VERSION 5.8 ;
BUSBITCHARS "[]" ;
DIVIDERCHAR "/" ;
UNITS
    DATABASE MICRONS 1000 ;
END UNITS

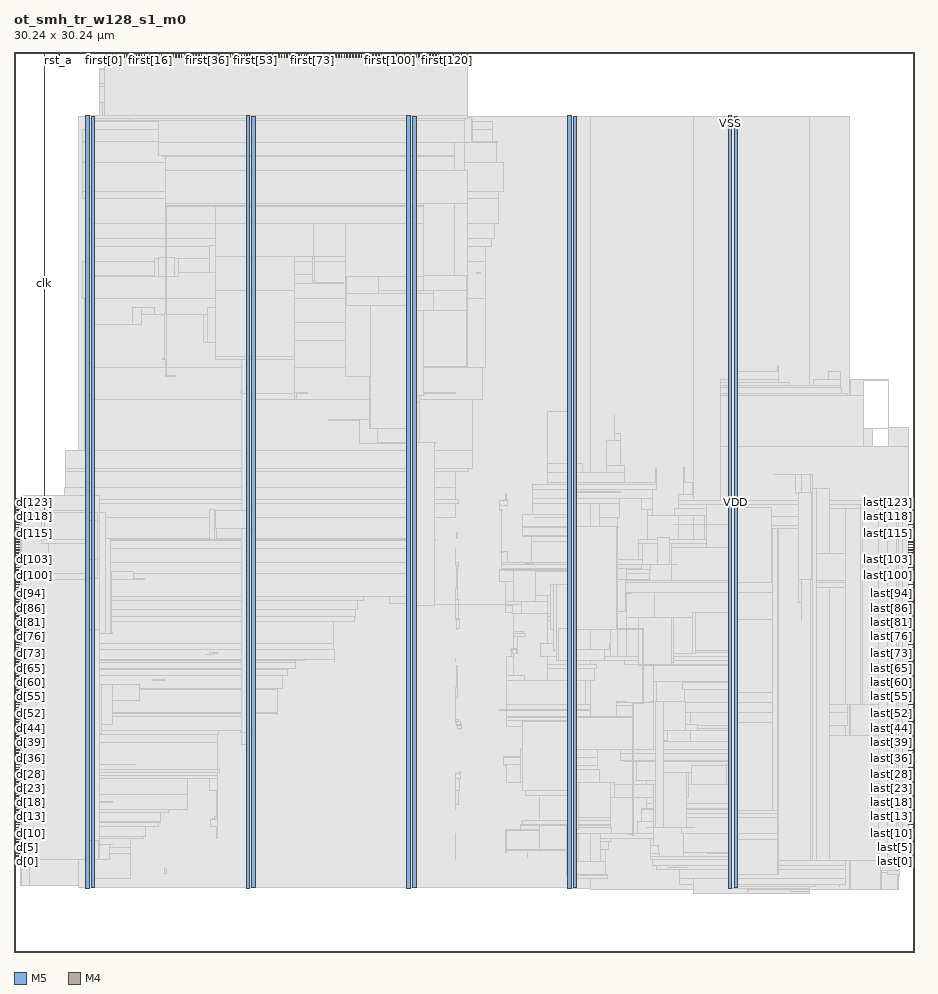
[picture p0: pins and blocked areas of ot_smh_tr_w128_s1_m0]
MACRO ot_smh_tr_w128_s1_m0
  FOREIGN ot_smh_tr_w128_s1_m0 0 0 ;
  CLASS BLOCK ;
  SIZE 30.24 BY 30.24 ;
  PIN clk
    DIRECTION INPUT ;
    USE SIGNAL ;
    PORT
      LAYER M5 ;
        RECT  1.008 30.048 1.032 30.24 ;
    END
    PORT
      LAYER M5 ;
        RECT  1.008 14.819 1.032 30.096 ;
    END
  END clk
  PIN d[0]
    DIRECTION INPUT ;
    USE SIGNAL ;
    PORT
      LAYER M4 ;
        RECT  0 3.024 0.192 3.048 ;
    END
  END d[0]
  PIN d[100]
    DIRECTION INPUT ;
    USE SIGNAL ;
    PORT
      LAYER M4 ;
        RECT  0 12.624 0.192 12.648 ;
    END
  END d[100]
  PIN d[101]
    DIRECTION INPUT ;
    USE SIGNAL ;
    PORT
      LAYER M4 ;
        RECT  0 12.72 0.192 12.744 ;
    END
  END d[101]
  PIN d[102]
    DIRECTION INPUT ;
    USE SIGNAL ;
    PORT
      LAYER M4 ;
        RECT  0 12.816 0.192 12.84 ;
    END
  END d[102]
  PIN d[103]
    DIRECTION INPUT ;
    USE SIGNAL ;
    PORT
      LAYER M4 ;
        RECT  0 12.912 0.192 12.936 ;
    END
  END d[103]
  PIN d[104]
    DIRECTION INPUT ;
    USE SIGNAL ;
    PORT
      LAYER M4 ;
        RECT  0 13.008 0.192 13.032 ;
    END
  END d[104]
  PIN d[105]
    DIRECTION INPUT ;
    USE SIGNAL ;
    PORT
      LAYER M4 ;
        RECT  0 13.104 0.192 13.128 ;
    END
  END d[105]
  PIN d[106]
    DIRECTION INPUT ;
    USE SIGNAL ;
    PORT
      LAYER M4 ;
        RECT  0 13.2 0.192 13.224 ;
    END
  END d[106]
  PIN d[107]
    DIRECTION INPUT ;
    USE SIGNAL ;
    PORT
      LAYER M4 ;
        RECT  0 13.296 0.192 13.32 ;
    END
  END d[107]
  PIN d[108]
    DIRECTION INPUT ;
    USE SIGNAL ;
    PORT
      LAYER M4 ;
        RECT  0 13.392 0.192 13.416 ;
    END
  END d[108]
  PIN d[109]
    DIRECTION INPUT ;
    USE SIGNAL ;
    PORT
      LAYER M4 ;
        RECT  0 13.488 0.192 13.512 ;
    END
  END d[109]
  PIN d[10]
    DIRECTION INPUT ;
    USE SIGNAL ;
    PORT
      LAYER M4 ;
        RECT  0 3.984 0.192 4.008 ;
    END
  END d[10]
  PIN d[110]
    DIRECTION INPUT ;
    USE SIGNAL ;
    PORT
      LAYER M4 ;
        RECT  0 13.584 0.192 13.608 ;
    END
  END d[110]
  PIN d[111]
    DIRECTION INPUT ;
    USE SIGNAL ;
    PORT
      LAYER M4 ;
        RECT  0 13.68 0.192 13.704 ;
    END
  END d[111]
  PIN d[112]
    DIRECTION INPUT ;
    USE SIGNAL ;
    PORT
      LAYER M4 ;
        RECT  0 13.776 0.192 13.8 ;
    END
  END d[112]
  PIN d[113]
    DIRECTION INPUT ;
    USE SIGNAL ;
    PORT
      LAYER M4 ;
        RECT  0 13.872 0.192 13.896 ;
    END
  END d[113]
  PIN d[114]
    DIRECTION INPUT ;
    USE SIGNAL ;
    PORT
      LAYER M4 ;
        RECT  0 13.968 0.192 13.992 ;
    END
  END d[114]
  PIN d[115]
    DIRECTION INPUT ;
    USE SIGNAL ;
    PORT
      LAYER M4 ;
        RECT  0 14.064 0.192 14.088 ;
    END
  END d[115]
  PIN d[116]
    DIRECTION INPUT ;
    USE SIGNAL ;
    PORT
      LAYER M4 ;
        RECT  0 14.16 0.192 14.184 ;
    END
  END d[116]
  PIN d[117]
    DIRECTION INPUT ;
    USE SIGNAL ;
    PORT
      LAYER M4 ;
        RECT  0 14.256 0.192 14.28 ;
    END
  END d[117]
  PIN d[118]
    DIRECTION INPUT ;
    USE SIGNAL ;
    PORT
      LAYER M4 ;
        RECT  0 14.352 0.192 14.376 ;
    END
  END d[118]
  PIN d[119]
    DIRECTION INPUT ;
    USE SIGNAL ;
    PORT
      LAYER M4 ;
        RECT  0 14.448 0.192 14.472 ;
    END
  END d[119]
  PIN d[11]
    DIRECTION INPUT ;
    USE SIGNAL ;
    PORT
      LAYER M4 ;
        RECT  0 4.08 0.192 4.104 ;
    END
  END d[11]
  PIN d[120]
    DIRECTION INPUT ;
    USE SIGNAL ;
    PORT
      LAYER M4 ;
        RECT  0 14.544 0.192 14.568 ;
    END
  END d[120]
  PIN d[121]
    DIRECTION INPUT ;
    USE SIGNAL ;
    PORT
      LAYER M4 ;
        RECT  0 14.64 0.192 14.664 ;
    END
  END d[121]
  PIN d[122]
    DIRECTION INPUT ;
    USE SIGNAL ;
    PORT
      LAYER M4 ;
        RECT  0 14.736 0.192 14.76 ;
    END
  END d[122]
  PIN d[123]
    DIRECTION INPUT ;
    USE SIGNAL ;
    PORT
      LAYER M4 ;
        RECT  0 14.832 0.192 14.856 ;
    END
  END d[123]
  PIN d[124]
    DIRECTION INPUT ;
    USE SIGNAL ;
    PORT
      LAYER M4 ;
        RECT  0 14.928 0.192 14.952 ;
    END
  END d[124]
  PIN d[125]
    DIRECTION INPUT ;
    USE SIGNAL ;
    PORT
      LAYER M4 ;
        RECT  0 15.024 0.192 15.048 ;
    END
  END d[125]
  PIN d[126]
    DIRECTION INPUT ;
    USE SIGNAL ;
    PORT
      LAYER M4 ;
        RECT  0 15.12 0.192 15.144 ;
    END
  END d[126]
  PIN d[127]
    DIRECTION INPUT ;
    USE SIGNAL ;
    PORT
      LAYER M4 ;
        RECT  0 15.216 0.192 15.24 ;
    END
  END d[127]
  PIN d[12]
    DIRECTION INPUT ;
    USE SIGNAL ;
    PORT
      LAYER M4 ;
        RECT  0 4.176 0.192 4.2 ;
    END
  END d[12]
  PIN d[13]
    DIRECTION INPUT ;
    USE SIGNAL ;
    PORT
      LAYER M4 ;
        RECT  0 4.272 0.192 4.296 ;
    END
  END d[13]
  PIN d[14]
    DIRECTION INPUT ;
    USE SIGNAL ;
    PORT
      LAYER M4 ;
        RECT  0 4.368 0.192 4.392 ;
    END
  END d[14]
  PIN d[15]
    DIRECTION INPUT ;
    USE SIGNAL ;
    PORT
      LAYER M4 ;
        RECT  0 4.464 0.192 4.488 ;
    END
  END d[15]
  PIN d[16]
    DIRECTION INPUT ;
    USE SIGNAL ;
    PORT
      LAYER M4 ;
        RECT  0 4.56 0.192 4.584 ;
    END
  END d[16]
  PIN d[17]
    DIRECTION INPUT ;
    USE SIGNAL ;
    PORT
      LAYER M4 ;
        RECT  0 4.656 0.192 4.68 ;
    END
  END d[17]
  PIN d[18]
    DIRECTION INPUT ;
    USE SIGNAL ;
    PORT
      LAYER M4 ;
        RECT  0 4.752 0.192 4.776 ;
    END
  END d[18]
  PIN d[19]
    DIRECTION INPUT ;
    USE SIGNAL ;
    PORT
      LAYER M4 ;
        RECT  0 4.848 0.192 4.872 ;
    END
  END d[19]
  PIN d[1]
    DIRECTION INPUT ;
    USE SIGNAL ;
    PORT
      LAYER M4 ;
        RECT  0 3.12 0.192 3.144 ;
    END
  END d[1]
  PIN d[20]
    DIRECTION INPUT ;
    USE SIGNAL ;
    PORT
      LAYER M4 ;
        RECT  0 4.944 0.192 4.968 ;
    END
  END d[20]
  PIN d[21]
    DIRECTION INPUT ;
    USE SIGNAL ;
    PORT
      LAYER M4 ;
        RECT  0 5.04 0.192 5.064 ;
    END
  END d[21]
  PIN d[22]
    DIRECTION INPUT ;
    USE SIGNAL ;
    PORT
      LAYER M4 ;
        RECT  0 5.136 0.192 5.16 ;
    END
  END d[22]
  PIN d[23]
    DIRECTION INPUT ;
    USE SIGNAL ;
    PORT
      LAYER M4 ;
        RECT  0 5.232 0.192 5.256 ;
    END
  END d[23]
  PIN d[24]
    DIRECTION INPUT ;
    USE SIGNAL ;
    PORT
      LAYER M4 ;
        RECT  0 5.328 0.192 5.352 ;
    END
  END d[24]
  PIN d[25]
    DIRECTION INPUT ;
    USE SIGNAL ;
    PORT
      LAYER M4 ;
        RECT  0 5.424 0.192 5.448 ;
    END
  END d[25]
  PIN d[26]
    DIRECTION INPUT ;
    USE SIGNAL ;
    PORT
      LAYER M4 ;
        RECT  0 5.52 0.192 5.544 ;
    END
  END d[26]
  PIN d[27]
    DIRECTION INPUT ;
    USE SIGNAL ;
    PORT
      LAYER M4 ;
        RECT  0 5.616 0.192 5.64 ;
    END
  END d[27]
  PIN d[28]
    DIRECTION INPUT ;
    USE SIGNAL ;
    PORT
      LAYER M4 ;
        RECT  0 5.712 0.192 5.736 ;
    END
  END d[28]
  PIN d[29]
    DIRECTION INPUT ;
    USE SIGNAL ;
    PORT
      LAYER M4 ;
        RECT  0 5.808 0.192 5.832 ;
    END
  END d[29]
  PIN d[2]
    DIRECTION INPUT ;
    USE SIGNAL ;
    PORT
      LAYER M4 ;
        RECT  0 3.216 0.192 3.24 ;
    END
  END d[2]
  PIN d[30]
    DIRECTION INPUT ;
    USE SIGNAL ;
    PORT
      LAYER M4 ;
        RECT  0 5.904 0.192 5.928 ;
    END
  END d[30]
  PIN d[31]
    DIRECTION INPUT ;
    USE SIGNAL ;
    PORT
      LAYER M4 ;
        RECT  0 6 0.192 6.024 ;
    END
  END d[31]
  PIN d[32]
    DIRECTION INPUT ;
    USE SIGNAL ;
    PORT
      LAYER M4 ;
        RECT  0 6.096 0.192 6.12 ;
    END
  END d[32]
  PIN d[33]
    DIRECTION INPUT ;
    USE SIGNAL ;
    PORT
      LAYER M4 ;
        RECT  0 6.192 0.192 6.216 ;
    END
  END d[33]
  PIN d[34]
    DIRECTION INPUT ;
    USE SIGNAL ;
    PORT
      LAYER M4 ;
        RECT  0 6.288 0.192 6.312 ;
    END
  END d[34]
  PIN d[35]
    DIRECTION INPUT ;
    USE SIGNAL ;
    PORT
      LAYER M4 ;
        RECT  0 6.384 0.192 6.408 ;
    END
  END d[35]
  PIN d[36]
    DIRECTION INPUT ;
    USE SIGNAL ;
    PORT
      LAYER M4 ;
        RECT  0 6.48 0.192 6.504 ;
    END
  END d[36]
  PIN d[37]
    DIRECTION INPUT ;
    USE SIGNAL ;
    PORT
      LAYER M4 ;
        RECT  0 6.576 0.192 6.6 ;
    END
  END d[37]
  PIN d[38]
    DIRECTION INPUT ;
    USE SIGNAL ;
    PORT
      LAYER M4 ;
        RECT  0 6.672 0.192 6.696 ;
    END
  END d[38]
  PIN d[39]
    DIRECTION INPUT ;
    USE SIGNAL ;
    PORT
      LAYER M4 ;
        RECT  0 6.768 0.192 6.792 ;
    END
  END d[39]
  PIN d[3]
    DIRECTION INPUT ;
    USE SIGNAL ;
    PORT
      LAYER M4 ;
        RECT  0 3.312 0.192 3.336 ;
    END
  END d[3]
  PIN d[40]
    DIRECTION INPUT ;
    USE SIGNAL ;
    PORT
      LAYER M4 ;
        RECT  0 6.864 0.192 6.888 ;
    END
  END d[40]
  PIN d[41]
    DIRECTION INPUT ;
    USE SIGNAL ;
    PORT
      LAYER M4 ;
        RECT  0 6.96 0.192 6.984 ;
    END
  END d[41]
  PIN d[42]
    DIRECTION INPUT ;
    USE SIGNAL ;
    PORT
      LAYER M4 ;
        RECT  0 7.056 0.192 7.08 ;
    END
  END d[42]
  PIN d[43]
    DIRECTION INPUT ;
    USE SIGNAL ;
    PORT
      LAYER M4 ;
        RECT  0 7.152 0.192 7.176 ;
    END
  END d[43]
  PIN d[44]
    DIRECTION INPUT ;
    USE SIGNAL ;
    PORT
      LAYER M4 ;
        RECT  0 7.248 0.192 7.272 ;
    END
  END d[44]
  PIN d[45]
    DIRECTION INPUT ;
    USE SIGNAL ;
    PORT
      LAYER M4 ;
        RECT  0 7.344 0.192 7.368 ;
    END
  END d[45]
  PIN d[46]
    DIRECTION INPUT ;
    USE SIGNAL ;
    PORT
      LAYER M4 ;
        RECT  0 7.44 0.192 7.464 ;
    END
  END d[46]
  PIN d[47]
    DIRECTION INPUT ;
    USE SIGNAL ;
    PORT
      LAYER M4 ;
        RECT  0 7.536 0.192 7.56 ;
    END
  END d[47]
  PIN d[48]
    DIRECTION INPUT ;
    USE SIGNAL ;
    PORT
      LAYER M4 ;
        RECT  0 7.632 0.192 7.656 ;
    END
  END d[48]
  PIN d[49]
    DIRECTION INPUT ;
    USE SIGNAL ;
    PORT
      LAYER M4 ;
        RECT  0 7.728 0.192 7.752 ;
    END
  END d[49]
  PIN d[4]
    DIRECTION INPUT ;
    USE SIGNAL ;
    PORT
      LAYER M4 ;
        RECT  0 3.408 0.192 3.432 ;
    END
  END d[4]
  PIN d[50]
    DIRECTION INPUT ;
    USE SIGNAL ;
    PORT
      LAYER M4 ;
        RECT  0 7.824 0.192 7.848 ;
    END
  END d[50]
  PIN d[51]
    DIRECTION INPUT ;
    USE SIGNAL ;
    PORT
      LAYER M4 ;
        RECT  0 7.92 0.192 7.944 ;
    END
  END d[51]
  PIN d[52]
    DIRECTION INPUT ;
    USE SIGNAL ;
    PORT
      LAYER M4 ;
        RECT  0 8.016 0.192 8.04 ;
    END
  END d[52]
  PIN d[53]
    DIRECTION INPUT ;
    USE SIGNAL ;
    PORT
      LAYER M4 ;
        RECT  0 8.112 0.192 8.136 ;
    END
  END d[53]
  PIN d[54]
    DIRECTION INPUT ;
    USE SIGNAL ;
    PORT
      LAYER M4 ;
        RECT  0 8.208 0.192 8.232 ;
    END
  END d[54]
  PIN d[55]
    DIRECTION INPUT ;
    USE SIGNAL ;
    PORT
      LAYER M4 ;
        RECT  0 8.304 0.192 8.328 ;
    END
  END d[55]
  PIN d[56]
    DIRECTION INPUT ;
    USE SIGNAL ;
    PORT
      LAYER M4 ;
        RECT  0 8.4 0.192 8.424 ;
    END
  END d[56]
  PIN d[57]
    DIRECTION INPUT ;
    USE SIGNAL ;
    PORT
      LAYER M4 ;
        RECT  0 8.496 0.192 8.52 ;
    END
  END d[57]
  PIN d[58]
    DIRECTION INPUT ;
    USE SIGNAL ;
    PORT
      LAYER M4 ;
        RECT  0 8.592 0.192 8.616 ;
    END
  END d[58]
  PIN d[59]
    DIRECTION INPUT ;
    USE SIGNAL ;
    PORT
      LAYER M4 ;
        RECT  0 8.688 0.192 8.712 ;
    END
  END d[59]
  PIN d[5]
    DIRECTION INPUT ;
    USE SIGNAL ;
    PORT
      LAYER M4 ;
        RECT  0 3.504 0.192 3.528 ;
    END
  END d[5]
  PIN d[60]
    DIRECTION INPUT ;
    USE SIGNAL ;
    PORT
      LAYER M4 ;
        RECT  0 8.784 0.192 8.808 ;
    END
  END d[60]
  PIN d[61]
    DIRECTION INPUT ;
    USE SIGNAL ;
    PORT
      LAYER M4 ;
        RECT  0 8.88 0.192 8.904 ;
    END
  END d[61]
  PIN d[62]
    DIRECTION INPUT ;
    USE SIGNAL ;
    PORT
      LAYER M4 ;
        RECT  0 8.976 0.192 9 ;
    END
  END d[62]
  PIN d[63]
    DIRECTION INPUT ;
    USE SIGNAL ;
    PORT
      LAYER M4 ;
        RECT  0 9.072 0.192 9.096 ;
    END
  END d[63]
  PIN d[64]
    DIRECTION INPUT ;
    USE SIGNAL ;
    PORT
      LAYER M4 ;
        RECT  0 9.168 0.192 9.192 ;
    END
  END d[64]
  PIN d[65]
    DIRECTION INPUT ;
    USE SIGNAL ;
    PORT
      LAYER M4 ;
        RECT  0 9.264 0.192 9.288 ;
    END
  END d[65]
  PIN d[66]
    DIRECTION INPUT ;
    USE SIGNAL ;
    PORT
      LAYER M4 ;
        RECT  0 9.36 0.192 9.384 ;
    END
  END d[66]
  PIN d[67]
    DIRECTION INPUT ;
    USE SIGNAL ;
    PORT
      LAYER M4 ;
        RECT  0 9.456 0.192 9.48 ;
    END
  END d[67]
  PIN d[68]
    DIRECTION INPUT ;
    USE SIGNAL ;
    PORT
      LAYER M4 ;
        RECT  0 9.552 0.192 9.576 ;
    END
  END d[68]
  PIN d[69]
    DIRECTION INPUT ;
    USE SIGNAL ;
    PORT
      LAYER M4 ;
        RECT  0 9.648 0.192 9.672 ;
    END
  END d[69]
  PIN d[6]
    DIRECTION INPUT ;
    USE SIGNAL ;
    PORT
      LAYER M4 ;
        RECT  0 3.6 0.192 3.624 ;
    END
  END d[6]
  PIN d[70]
    DIRECTION INPUT ;
    USE SIGNAL ;
    PORT
      LAYER M4 ;
        RECT  0 9.744 0.192 9.768 ;
    END
  END d[70]
  PIN d[71]
    DIRECTION INPUT ;
    USE SIGNAL ;
    PORT
      LAYER M4 ;
        RECT  0 9.84 0.192 9.864 ;
    END
  END d[71]
  PIN d[72]
    DIRECTION INPUT ;
    USE SIGNAL ;
    PORT
      LAYER M4 ;
        RECT  0 9.936 0.192 9.96 ;
    END
  END d[72]
  PIN d[73]
    DIRECTION INPUT ;
    USE SIGNAL ;
    PORT
      LAYER M4 ;
        RECT  0 10.032 0.192 10.056 ;
    END
  END d[73]
  PIN d[74]
    DIRECTION INPUT ;
    USE SIGNAL ;
    PORT
      LAYER M4 ;
        RECT  0 10.128 0.192 10.152 ;
    END
  END d[74]
  PIN d[75]
    DIRECTION INPUT ;
    USE SIGNAL ;
    PORT
      LAYER M4 ;
        RECT  0 10.224 0.192 10.248 ;
    END
  END d[75]
  PIN d[76]
    DIRECTION INPUT ;
    USE SIGNAL ;
    PORT
      LAYER M4 ;
        RECT  0 10.32 0.192 10.344 ;
    END
  END d[76]
  PIN d[77]
    DIRECTION INPUT ;
    USE SIGNAL ;
    PORT
      LAYER M4 ;
        RECT  0 10.416 0.192 10.44 ;
    END
  END d[77]
  PIN d[78]
    DIRECTION INPUT ;
    USE SIGNAL ;
    PORT
      LAYER M4 ;
        RECT  0 10.512 0.192 10.536 ;
    END
  END d[78]
  PIN d[79]
    DIRECTION INPUT ;
    USE SIGNAL ;
    PORT
      LAYER M4 ;
        RECT  0 10.608 0.192 10.632 ;
    END
  END d[79]
  PIN d[7]
    DIRECTION INPUT ;
    USE SIGNAL ;
    PORT
      LAYER M4 ;
        RECT  0 3.696 0.192 3.72 ;
    END
  END d[7]
  PIN d[80]
    DIRECTION INPUT ;
    USE SIGNAL ;
    PORT
      LAYER M4 ;
        RECT  0 10.704 0.192 10.728 ;
    END
  END d[80]
  PIN d[81]
    DIRECTION INPUT ;
    USE SIGNAL ;
    PORT
      LAYER M4 ;
        RECT  0 10.8 0.192 10.824 ;
    END
  END d[81]
  PIN d[82]
    DIRECTION INPUT ;
    USE SIGNAL ;
    PORT
      LAYER M4 ;
        RECT  0 10.896 0.192 10.92 ;
    END
  END d[82]
  PIN d[83]
    DIRECTION INPUT ;
    USE SIGNAL ;
    PORT
      LAYER M4 ;
        RECT  0 10.992 0.192 11.016 ;
    END
  END d[83]
  PIN d[84]
    DIRECTION INPUT ;
    USE SIGNAL ;
    PORT
      LAYER M4 ;
        RECT  0 11.088 0.192 11.112 ;
    END
  END d[84]
  PIN d[85]
    DIRECTION INPUT ;
    USE SIGNAL ;
    PORT
      LAYER M4 ;
        RECT  0 11.184 0.192 11.208 ;
    END
  END d[85]
  PIN d[86]
    DIRECTION INPUT ;
    USE SIGNAL ;
    PORT
      LAYER M4 ;
        RECT  0 11.28 0.192 11.304 ;
    END
  END d[86]
  PIN d[87]
    DIRECTION INPUT ;
    USE SIGNAL ;
    PORT
      LAYER M4 ;
        RECT  0 11.376 0.192 11.4 ;
    END
  END d[87]
  PIN d[88]
    DIRECTION INPUT ;
    USE SIGNAL ;
    PORT
      LAYER M4 ;
        RECT  0 11.472 0.192 11.496 ;
    END
  END d[88]
  PIN d[89]
    DIRECTION INPUT ;
    USE SIGNAL ;
    PORT
      LAYER M4 ;
        RECT  0 11.568 0.192 11.592 ;
    END
  END d[89]
  PIN d[8]
    DIRECTION INPUT ;
    USE SIGNAL ;
    PORT
      LAYER M4 ;
        RECT  0 3.792 0.192 3.816 ;
    END
  END d[8]
  PIN d[90]
    DIRECTION INPUT ;
    USE SIGNAL ;
    PORT
      LAYER M4 ;
        RECT  0 11.664 0.192 11.688 ;
    END
  END d[90]
  PIN d[91]
    DIRECTION INPUT ;
    USE SIGNAL ;
    PORT
      LAYER M4 ;
        RECT  0 11.76 0.192 11.784 ;
    END
  END d[91]
  PIN d[92]
    DIRECTION INPUT ;
    USE SIGNAL ;
    PORT
      LAYER M4 ;
        RECT  0 11.856 0.192 11.88 ;
    END
  END d[92]
  PIN d[93]
    DIRECTION INPUT ;
    USE SIGNAL ;
    PORT
      LAYER M4 ;
        RECT  0 11.952 0.192 11.976 ;
    END
  END d[93]
  PIN d[94]
    DIRECTION INPUT ;
    USE SIGNAL ;
    PORT
      LAYER M4 ;
        RECT  0 12.048 0.192 12.072 ;
    END
  END d[94]
  PIN d[95]
    DIRECTION INPUT ;
    USE SIGNAL ;
    PORT
      LAYER M4 ;
        RECT  0 12.144 0.192 12.168 ;
    END
  END d[95]
  PIN d[96]
    DIRECTION INPUT ;
    USE SIGNAL ;
    PORT
      LAYER M4 ;
        RECT  0 12.24 0.192 12.264 ;
    END
  END d[96]
  PIN d[97]
    DIRECTION INPUT ;
    USE SIGNAL ;
    PORT
      LAYER M4 ;
        RECT  0 12.336 0.192 12.36 ;
    END
  END d[97]
  PIN d[98]
    DIRECTION INPUT ;
    USE SIGNAL ;
    PORT
      LAYER M4 ;
        RECT  0 12.432 0.192 12.456 ;
    END
  END d[98]
  PIN d[99]
    DIRECTION INPUT ;
    USE SIGNAL ;
    PORT
      LAYER M4 ;
        RECT  0 12.528 0.192 12.552 ;
    END
  END d[99]
  PIN d[9]
    DIRECTION INPUT ;
    USE SIGNAL ;
    PORT
      LAYER M4 ;
        RECT  0 3.888 0.192 3.912 ;
    END
  END d[9]
  PIN first[0]
    DIRECTION OUTPUT ;
    USE SIGNAL ;
    PORT
      LAYER M5 ;
        RECT  3.024 30.048 3.048 30.24 ;
    END
  END first[0]
  PIN first[100]
    DIRECTION OUTPUT ;
    USE SIGNAL ;
    PORT
      LAYER M5 ;
        RECT  12.624 30.048 12.648 30.24 ;
    END
  END first[100]
  PIN first[101]
    DIRECTION OUTPUT ;
    USE SIGNAL ;
    PORT
      LAYER M5 ;
        RECT  12.72 30.048 12.744 30.24 ;
    END
  END first[101]
  PIN first[102]
    DIRECTION OUTPUT ;
    USE SIGNAL ;
    PORT
      LAYER M5 ;
        RECT  12.816 30.048 12.84 30.24 ;
    END
  END first[102]
  PIN first[103]
    DIRECTION OUTPUT ;
    USE SIGNAL ;
    PORT
      LAYER M5 ;
        RECT  12.912 30.048 12.936 30.24 ;
    END
  END first[103]
  PIN first[104]
    DIRECTION OUTPUT ;
    USE SIGNAL ;
    PORT
      LAYER M5 ;
        RECT  13.008 30.048 13.032 30.24 ;
    END
  END first[104]
  PIN first[105]
    DIRECTION OUTPUT ;
    USE SIGNAL ;
    PORT
      LAYER M5 ;
        RECT  13.104 30.048 13.128 30.24 ;
    END
  END first[105]
  PIN first[106]
    DIRECTION OUTPUT ;
    USE SIGNAL ;
    PORT
      LAYER M5 ;
        RECT  13.2 30.048 13.224 30.24 ;
    END
  END first[106]
  PIN first[107]
    DIRECTION OUTPUT ;
    USE SIGNAL ;
    PORT
      LAYER M5 ;
        RECT  13.296 30.048 13.32 30.24 ;
    END
  END first[107]
  PIN first[108]
    DIRECTION OUTPUT ;
    USE SIGNAL ;
    PORT
      LAYER M5 ;
        RECT  13.392 30.048 13.416 30.24 ;
    END
  END first[108]
  PIN first[109]
    DIRECTION OUTPUT ;
    USE SIGNAL ;
    PORT
      LAYER M5 ;
        RECT  13.488 30.048 13.512 30.24 ;
    END
  END first[109]
  PIN first[10]
    DIRECTION OUTPUT ;
    USE SIGNAL ;
    PORT
      LAYER M5 ;
        RECT  3.984 30.048 4.008 30.24 ;
    END
  END first[10]
  PIN first[110]
    DIRECTION OUTPUT ;
    USE SIGNAL ;
    PORT
      LAYER M5 ;
        RECT  13.584 30.048 13.608 30.24 ;
    END
  END first[110]
  PIN first[111]
    DIRECTION OUTPUT ;
    USE SIGNAL ;
    PORT
      LAYER M5 ;
        RECT  13.68 30.048 13.704 30.24 ;
    END
  END first[111]
  PIN first[112]
    DIRECTION OUTPUT ;
    USE SIGNAL ;
    PORT
      LAYER M5 ;
        RECT  13.776 30.048 13.8 30.24 ;
    END
  END first[112]
  PIN first[113]
    DIRECTION OUTPUT ;
    USE SIGNAL ;
    PORT
      LAYER M5 ;
        RECT  13.872 30.048 13.896 30.24 ;
    END
  END first[113]
  PIN first[114]
    DIRECTION OUTPUT ;
    USE SIGNAL ;
    PORT
      LAYER M5 ;
        RECT  13.968 30.048 13.992 30.24 ;
    END
  END first[114]
  PIN first[115]
    DIRECTION OUTPUT ;
    USE SIGNAL ;
    PORT
      LAYER M5 ;
        RECT  14.064 30.048 14.088 30.24 ;
    END
  END first[115]
  PIN first[116]
    DIRECTION OUTPUT ;
    USE SIGNAL ;
    PORT
      LAYER M5 ;
        RECT  14.16 30.048 14.184 30.24 ;
    END
  END first[116]
  PIN first[117]
    DIRECTION OUTPUT ;
    USE SIGNAL ;
    PORT
      LAYER M5 ;
        RECT  14.256 30.048 14.28 30.24 ;
    END
  END first[117]
  PIN first[118]
    DIRECTION OUTPUT ;
    USE SIGNAL ;
    PORT
      LAYER M5 ;
        RECT  14.352 30.048 14.376 30.24 ;
    END
  END first[118]
  PIN first[119]
    DIRECTION OUTPUT ;
    USE SIGNAL ;
    PORT
      LAYER M5 ;
        RECT  14.448 30.048 14.472 30.24 ;
    END
  END first[119]
  PIN first[11]
    DIRECTION OUTPUT ;
    USE SIGNAL ;
    PORT
      LAYER M5 ;
        RECT  4.08 30.048 4.104 30.24 ;
    END
  END first[11]
  PIN first[120]
    DIRECTION OUTPUT ;
    USE SIGNAL ;
    PORT
      LAYER M5 ;
        RECT  14.544 30.048 14.568 30.24 ;
    END
  END first[120]
  PIN first[121]
    DIRECTION OUTPUT ;
    USE SIGNAL ;
    PORT
      LAYER M5 ;
        RECT  14.64 30.048 14.664 30.24 ;
    END
  END first[121]
  PIN first[122]
    DIRECTION OUTPUT ;
    USE SIGNAL ;
    PORT
      LAYER M5 ;
        RECT  14.736 30.048 14.76 30.24 ;
    END
  END first[122]
  PIN first[123]
    DIRECTION OUTPUT ;
    USE SIGNAL ;
    PORT
      LAYER M5 ;
        RECT  14.832 30.048 14.856 30.24 ;
    END
  END first[123]
  PIN first[124]
    DIRECTION OUTPUT ;
    USE SIGNAL ;
    PORT
      LAYER M5 ;
        RECT  14.928 30.048 14.952 30.24 ;
    END
  END first[124]
  PIN first[125]
    DIRECTION OUTPUT ;
    USE SIGNAL ;
    PORT
      LAYER M5 ;
        RECT  15.024 30.048 15.048 30.24 ;
    END
  END first[125]
  PIN first[126]
    DIRECTION OUTPUT ;
    USE SIGNAL ;
    PORT
      LAYER M5 ;
        RECT  15.12 30.048 15.144 30.24 ;
    END
  END first[126]
  PIN first[127]
    DIRECTION OUTPUT ;
    USE SIGNAL ;
    PORT
      LAYER M5 ;
        RECT  15.216 30.048 15.24 30.24 ;
    END
  END first[127]
  PIN first[12]
    DIRECTION OUTPUT ;
    USE SIGNAL ;
    PORT
      LAYER M5 ;
        RECT  4.176 30.048 4.2 30.24 ;
    END
  END first[12]
  PIN first[13]
    DIRECTION OUTPUT ;
    USE SIGNAL ;
    PORT
      LAYER M5 ;
        RECT  4.272 30.048 4.296 30.24 ;
    END
  END first[13]
  PIN first[14]
    DIRECTION OUTPUT ;
    USE SIGNAL ;
    PORT
      LAYER M5 ;
        RECT  4.368 30.048 4.392 30.24 ;
    END
  END first[14]
  PIN first[15]
    DIRECTION OUTPUT ;
    USE SIGNAL ;
    PORT
      LAYER M5 ;
        RECT  4.464 30.048 4.488 30.24 ;
    END
  END first[15]
  PIN first[16]
    DIRECTION OUTPUT ;
    USE SIGNAL ;
    PORT
      LAYER M5 ;
        RECT  4.56 30.048 4.584 30.24 ;
    END
  END first[16]
  PIN first[17]
    DIRECTION OUTPUT ;
    USE SIGNAL ;
    PORT
      LAYER M5 ;
        RECT  4.656 30.048 4.68 30.24 ;
    END
  END first[17]
  PIN first[18]
    DIRECTION OUTPUT ;
    USE SIGNAL ;
    PORT
      LAYER M5 ;
        RECT  4.752 30.048 4.776 30.24 ;
    END
  END first[18]
  PIN first[19]
    DIRECTION OUTPUT ;
    USE SIGNAL ;
    PORT
      LAYER M5 ;
        RECT  4.848 30.048 4.872 30.24 ;
    END
  END first[19]
  PIN first[1]
    DIRECTION OUTPUT ;
    USE SIGNAL ;
    PORT
      LAYER M5 ;
        RECT  3.12 30.048 3.144 30.24 ;
    END
  END first[1]
  PIN first[20]
    DIRECTION OUTPUT ;
    USE SIGNAL ;
    PORT
      LAYER M5 ;
        RECT  4.944 30.048 4.968 30.24 ;
    END
  END first[20]
  PIN first[21]
    DIRECTION OUTPUT ;
    USE SIGNAL ;
    PORT
      LAYER M5 ;
        RECT  5.04 30.048 5.064 30.24 ;
    END
  END first[21]
  PIN first[22]
    DIRECTION OUTPUT ;
    USE SIGNAL ;
    PORT
      LAYER M5 ;
        RECT  5.136 30.048 5.16 30.24 ;
    END
  END first[22]
  PIN first[23]
    DIRECTION OUTPUT ;
    USE SIGNAL ;
    PORT
      LAYER M5 ;
        RECT  5.232 30.048 5.256 30.24 ;
    END
  END first[23]
  PIN first[24]
    DIRECTION OUTPUT ;
    USE SIGNAL ;
    PORT
      LAYER M5 ;
        RECT  5.328 30.048 5.352 30.24 ;
    END
  END first[24]
  PIN first[25]
    DIRECTION OUTPUT ;
    USE SIGNAL ;
    PORT
      LAYER M5 ;
        RECT  5.424 30.048 5.448 30.24 ;
    END
  END first[25]
  PIN first[26]
    DIRECTION OUTPUT ;
    USE SIGNAL ;
    PORT
      LAYER M5 ;
        RECT  5.52 30.048 5.544 30.24 ;
    END
  END first[26]
  PIN first[27]
    DIRECTION OUTPUT ;
    USE SIGNAL ;
    PORT
      LAYER M5 ;
        RECT  5.616 30.048 5.64 30.24 ;
    END
  END first[27]
  PIN first[28]
    DIRECTION OUTPUT ;
    USE SIGNAL ;
    PORT
      LAYER M5 ;
        RECT  5.712 30.048 5.736 30.24 ;
    END
  END first[28]
  PIN first[29]
    DIRECTION OUTPUT ;
    USE SIGNAL ;
    PORT
      LAYER M5 ;
        RECT  5.808 30.048 5.832 30.24 ;
    END
  END first[29]
  PIN first[2]
    DIRECTION OUTPUT ;
    USE SIGNAL ;
    PORT
      LAYER M5 ;
        RECT  3.216 30.048 3.24 30.24 ;
    END
  END first[2]
  PIN first[30]
    DIRECTION OUTPUT ;
    USE SIGNAL ;
    PORT
      LAYER M5 ;
        RECT  5.904 30.048 5.928 30.24 ;
    END
  END first[30]
  PIN first[31]
    DIRECTION OUTPUT ;
    USE SIGNAL ;
    PORT
      LAYER M5 ;
        RECT  6 30.048 6.024 30.24 ;
    END
  END first[31]
  PIN first[32]
    DIRECTION OUTPUT ;
    USE SIGNAL ;
    PORT
      LAYER M5 ;
        RECT  6.096 30.048 6.12 30.24 ;
    END
  END first[32]
  PIN first[33]
    DIRECTION OUTPUT ;
    USE SIGNAL ;
    PORT
      LAYER M5 ;
        RECT  6.192 30.048 6.216 30.24 ;
    END
  END first[33]
  PIN first[34]
    DIRECTION OUTPUT ;
    USE SIGNAL ;
    PORT
      LAYER M5 ;
        RECT  6.288 30.048 6.312 30.24 ;
    END
  END first[34]
  PIN first[35]
    DIRECTION OUTPUT ;
    USE SIGNAL ;
    PORT
      LAYER M5 ;
        RECT  6.384 30.048 6.408 30.24 ;
    END
  END first[35]
  PIN first[36]
    DIRECTION OUTPUT ;
    USE SIGNAL ;
    PORT
      LAYER M5 ;
        RECT  6.48 30.048 6.504 30.24 ;
    END
  END first[36]
  PIN first[37]
    DIRECTION OUTPUT ;
    USE SIGNAL ;
    PORT
      LAYER M5 ;
        RECT  6.576 30.048 6.6 30.24 ;
    END
  END first[37]
  PIN first[38]
    DIRECTION OUTPUT ;
    USE SIGNAL ;
    PORT
      LAYER M5 ;
        RECT  6.672 30.048 6.696 30.24 ;
    END
  END first[38]
  PIN first[39]
    DIRECTION OUTPUT ;
    USE SIGNAL ;
    PORT
      LAYER M5 ;
        RECT  6.768 30.048 6.792 30.24 ;
    END
  END first[39]
  PIN first[3]
    DIRECTION OUTPUT ;
    USE SIGNAL ;
    PORT
      LAYER M5 ;
        RECT  3.312 30.048 3.336 30.24 ;
    END
  END first[3]
  PIN first[40]
    DIRECTION OUTPUT ;
    USE SIGNAL ;
    PORT
      LAYER M5 ;
        RECT  6.864 30.048 6.888 30.24 ;
    END
  END first[40]
  PIN first[41]
    DIRECTION OUTPUT ;
    USE SIGNAL ;
    PORT
      LAYER M5 ;
        RECT  6.96 30.048 6.984 30.24 ;
    END
  END first[41]
  PIN first[42]
    DIRECTION OUTPUT ;
    USE SIGNAL ;
    PORT
      LAYER M5 ;
        RECT  7.056 30.048 7.08 30.24 ;
    END
  END first[42]
  PIN first[43]
    DIRECTION OUTPUT ;
    USE SIGNAL ;
    PORT
      LAYER M5 ;
        RECT  7.152 30.048 7.176 30.24 ;
    END
  END first[43]
  PIN first[44]
    DIRECTION OUTPUT ;
    USE SIGNAL ;
    PORT
      LAYER M5 ;
        RECT  7.248 30.048 7.272 30.24 ;
    END
  END first[44]
  PIN first[45]
    DIRECTION OUTPUT ;
    USE SIGNAL ;
    PORT
      LAYER M5 ;
        RECT  7.344 30.048 7.368 30.24 ;
    END
  END first[45]
  PIN first[46]
    DIRECTION OUTPUT ;
    USE SIGNAL ;
    PORT
      LAYER M5 ;
        RECT  7.44 30.048 7.464 30.24 ;
    END
  END first[46]
  PIN first[47]
    DIRECTION OUTPUT ;
    USE SIGNAL ;
    PORT
      LAYER M5 ;
        RECT  7.536 30.048 7.56 30.24 ;
    END
  END first[47]
  PIN first[48]
    DIRECTION OUTPUT ;
    USE SIGNAL ;
    PORT
      LAYER M5 ;
        RECT  7.632 30.048 7.656 30.24 ;
    END
  END first[48]
  PIN first[49]
    DIRECTION OUTPUT ;
    USE SIGNAL ;
    PORT
      LAYER M5 ;
        RECT  7.728 30.048 7.752 30.24 ;
    END
  END first[49]
  PIN first[4]
    DIRECTION OUTPUT ;
    USE SIGNAL ;
    PORT
      LAYER M5 ;
        RECT  3.408 30.048 3.432 30.24 ;
    END
  END first[4]
  PIN first[50]
    DIRECTION OUTPUT ;
    USE SIGNAL ;
    PORT
      LAYER M5 ;
        RECT  7.824 30.048 7.848 30.24 ;
    END
  END first[50]
  PIN first[51]
    DIRECTION OUTPUT ;
    USE SIGNAL ;
    PORT
      LAYER M5 ;
        RECT  7.92 30.048 7.944 30.24 ;
    END
  END first[51]
  PIN first[52]
    DIRECTION OUTPUT ;
    USE SIGNAL ;
    PORT
      LAYER M5 ;
        RECT  8.016 30.048 8.04 30.24 ;
    END
  END first[52]
  PIN first[53]
    DIRECTION OUTPUT ;
    USE SIGNAL ;
    PORT
      LAYER M5 ;
        RECT  8.112 30.048 8.136 30.24 ;
    END
  END first[53]
  PIN first[54]
    DIRECTION OUTPUT ;
    USE SIGNAL ;
    PORT
      LAYER M5 ;
        RECT  8.208 30.048 8.232 30.24 ;
    END
  END first[54]
  PIN first[55]
    DIRECTION OUTPUT ;
    USE SIGNAL ;
    PORT
      LAYER M5 ;
        RECT  8.304 30.048 8.328 30.24 ;
    END
  END first[55]
  PIN first[56]
    DIRECTION OUTPUT ;
    USE SIGNAL ;
    PORT
      LAYER M5 ;
        RECT  8.4 30.048 8.424 30.24 ;
    END
  END first[56]
  PIN first[57]
    DIRECTION OUTPUT ;
    USE SIGNAL ;
    PORT
      LAYER M5 ;
        RECT  8.496 30.048 8.52 30.24 ;
    END
  END first[57]
  PIN first[58]
    DIRECTION OUTPUT ;
    USE SIGNAL ;
    PORT
      LAYER M5 ;
        RECT  8.592 30.048 8.616 30.24 ;
    END
  END first[58]
  PIN first[59]
    DIRECTION OUTPUT ;
    USE SIGNAL ;
    PORT
      LAYER M5 ;
        RECT  8.688 30.048 8.712 30.24 ;
    END
  END first[59]
  PIN first[5]
    DIRECTION OUTPUT ;
    USE SIGNAL ;
    PORT
      LAYER M5 ;
        RECT  3.504 30.048 3.528 30.24 ;
    END
  END first[5]
  PIN first[60]
    DIRECTION OUTPUT ;
    USE SIGNAL ;
    PORT
      LAYER M5 ;
        RECT  8.784 30.048 8.808 30.24 ;
    END
  END first[60]
  PIN first[61]
    DIRECTION OUTPUT ;
    USE SIGNAL ;
    PORT
      LAYER M5 ;
        RECT  8.88 30.048 8.904 30.24 ;
    END
  END first[61]
  PIN first[62]
    DIRECTION OUTPUT ;
    USE SIGNAL ;
    PORT
      LAYER M5 ;
        RECT  8.976 30.048 9 30.24 ;
    END
  END first[62]
  PIN first[63]
    DIRECTION OUTPUT ;
    USE SIGNAL ;
    PORT
      LAYER M5 ;
        RECT  9.072 30.048 9.096 30.24 ;
    END
  END first[63]
  PIN first[64]
    DIRECTION OUTPUT ;
    USE SIGNAL ;
    PORT
      LAYER M5 ;
        RECT  9.168 30.048 9.192 30.24 ;
    END
  END first[64]
  PIN first[65]
    DIRECTION OUTPUT ;
    USE SIGNAL ;
    PORT
      LAYER M5 ;
        RECT  9.264 30.048 9.288 30.24 ;
    END
  END first[65]
  PIN first[66]
    DIRECTION OUTPUT ;
    USE SIGNAL ;
    PORT
      LAYER M5 ;
        RECT  9.36 30.048 9.384 30.24 ;
    END
  END first[66]
  PIN first[67]
    DIRECTION OUTPUT ;
    USE SIGNAL ;
    PORT
      LAYER M5 ;
        RECT  9.456 30.048 9.48 30.24 ;
    END
  END first[67]
  PIN first[68]
    DIRECTION OUTPUT ;
    USE SIGNAL ;
    PORT
      LAYER M5 ;
        RECT  9.552 30.048 9.576 30.24 ;
    END
  END first[68]
  PIN first[69]
    DIRECTION OUTPUT ;
    USE SIGNAL ;
    PORT
      LAYER M5 ;
        RECT  9.648 30.048 9.672 30.24 ;
    END
  END first[69]
  PIN first[6]
    DIRECTION OUTPUT ;
    USE SIGNAL ;
    PORT
      LAYER M5 ;
        RECT  3.6 30.048 3.624 30.24 ;
    END
  END first[6]
  PIN first[70]
    DIRECTION OUTPUT ;
    USE SIGNAL ;
    PORT
      LAYER M5 ;
        RECT  9.744 30.048 9.768 30.24 ;
    END
  END first[70]
  PIN first[71]
    DIRECTION OUTPUT ;
    USE SIGNAL ;
    PORT
      LAYER M5 ;
        RECT  9.84 30.048 9.864 30.24 ;
    END
  END first[71]
  PIN first[72]
    DIRECTION OUTPUT ;
    USE SIGNAL ;
    PORT
      LAYER M5 ;
        RECT  9.936 30.048 9.96 30.24 ;
    END
  END first[72]
  PIN first[73]
    DIRECTION OUTPUT ;
    USE SIGNAL ;
    PORT
      LAYER M5 ;
        RECT  10.032 30.048 10.056 30.24 ;
    END
  END first[73]
  PIN first[74]
    DIRECTION OUTPUT ;
    USE SIGNAL ;
    PORT
      LAYER M5 ;
        RECT  10.128 30.048 10.152 30.24 ;
    END
  END first[74]
  PIN first[75]
    DIRECTION OUTPUT ;
    USE SIGNAL ;
    PORT
      LAYER M5 ;
        RECT  10.224 30.048 10.248 30.24 ;
    END
  END first[75]
  PIN first[76]
    DIRECTION OUTPUT ;
    USE SIGNAL ;
    PORT
      LAYER M5 ;
        RECT  10.32 30.048 10.344 30.24 ;
    END
  END first[76]
  PIN first[77]
    DIRECTION OUTPUT ;
    USE SIGNAL ;
    PORT
      LAYER M5 ;
        RECT  10.416 30.048 10.44 30.24 ;
    END
  END first[77]
  PIN first[78]
    DIRECTION OUTPUT ;
    USE SIGNAL ;
    PORT
      LAYER M5 ;
        RECT  10.512 30.048 10.536 30.24 ;
    END
  END first[78]
  PIN first[79]
    DIRECTION OUTPUT ;
    USE SIGNAL ;
    PORT
      LAYER M5 ;
        RECT  10.608 30.048 10.632 30.24 ;
    END
  END first[79]
  PIN first[7]
    DIRECTION OUTPUT ;
    USE SIGNAL ;
    PORT
      LAYER M5 ;
        RECT  3.696 30.048 3.72 30.24 ;
    END
  END first[7]
  PIN first[80]
    DIRECTION OUTPUT ;
    USE SIGNAL ;
    PORT
      LAYER M5 ;
        RECT  10.704 30.048 10.728 30.24 ;
    END
  END first[80]
  PIN first[81]
    DIRECTION OUTPUT ;
    USE SIGNAL ;
    PORT
      LAYER M5 ;
        RECT  10.8 30.048 10.824 30.24 ;
    END
  END first[81]
  PIN first[82]
    DIRECTION OUTPUT ;
    USE SIGNAL ;
    PORT
      LAYER M5 ;
        RECT  10.896 30.048 10.92 30.24 ;
    END
  END first[82]
  PIN first[83]
    DIRECTION OUTPUT ;
    USE SIGNAL ;
    PORT
      LAYER M5 ;
        RECT  10.992 30.048 11.016 30.24 ;
    END
  END first[83]
  PIN first[84]
    DIRECTION OUTPUT ;
    USE SIGNAL ;
    PORT
      LAYER M5 ;
        RECT  11.088 30.048 11.112 30.24 ;
    END
  END first[84]
  PIN first[85]
    DIRECTION OUTPUT ;
    USE SIGNAL ;
    PORT
      LAYER M5 ;
        RECT  11.184 30.048 11.208 30.24 ;
    END
  END first[85]
  PIN first[86]
    DIRECTION OUTPUT ;
    USE SIGNAL ;
    PORT
      LAYER M5 ;
        RECT  11.28 30.048 11.304 30.24 ;
    END
  END first[86]
  PIN first[87]
    DIRECTION OUTPUT ;
    USE SIGNAL ;
    PORT
      LAYER M5 ;
        RECT  11.376 30.048 11.4 30.24 ;
    END
  END first[87]
  PIN first[88]
    DIRECTION OUTPUT ;
    USE SIGNAL ;
    PORT
      LAYER M5 ;
        RECT  11.472 30.048 11.496 30.24 ;
    END
  END first[88]
  PIN first[89]
    DIRECTION OUTPUT ;
    USE SIGNAL ;
    PORT
      LAYER M5 ;
        RECT  11.568 30.048 11.592 30.24 ;
    END
  END first[89]
  PIN first[8]
    DIRECTION OUTPUT ;
    USE SIGNAL ;
    PORT
      LAYER M5 ;
        RECT  3.792 30.048 3.816 30.24 ;
    END
  END first[8]
  PIN first[90]
    DIRECTION OUTPUT ;
    USE SIGNAL ;
    PORT
      LAYER M5 ;
        RECT  11.664 30.048 11.688 30.24 ;
    END
  END first[90]
  PIN first[91]
    DIRECTION OUTPUT ;
    USE SIGNAL ;
    PORT
      LAYER M5 ;
        RECT  11.76 30.048 11.784 30.24 ;
    END
  END first[91]
  PIN first[92]
    DIRECTION OUTPUT ;
    USE SIGNAL ;
    PORT
      LAYER M5 ;
        RECT  11.856 30.048 11.88 30.24 ;
    END
  END first[92]
  PIN first[93]
    DIRECTION OUTPUT ;
    USE SIGNAL ;
    PORT
      LAYER M5 ;
        RECT  11.952 30.048 11.976 30.24 ;
    END
  END first[93]
  PIN first[94]
    DIRECTION OUTPUT ;
    USE SIGNAL ;
    PORT
      LAYER M5 ;
        RECT  12.048 30.048 12.072 30.24 ;
    END
  END first[94]
  PIN first[95]
    DIRECTION OUTPUT ;
    USE SIGNAL ;
    PORT
      LAYER M5 ;
        RECT  12.144 30.048 12.168 30.24 ;
    END
  END first[95]
  PIN first[96]
    DIRECTION OUTPUT ;
    USE SIGNAL ;
    PORT
      LAYER M5 ;
        RECT  12.24 30.048 12.264 30.24 ;
    END
  END first[96]
  PIN first[97]
    DIRECTION OUTPUT ;
    USE SIGNAL ;
    PORT
      LAYER M5 ;
        RECT  12.336 30.048 12.36 30.24 ;
    END
  END first[97]
  PIN first[98]
    DIRECTION OUTPUT ;
    USE SIGNAL ;
    PORT
      LAYER M5 ;
        RECT  12.432 30.048 12.456 30.24 ;
    END
  END first[98]
  PIN first[99]
    DIRECTION OUTPUT ;
    USE SIGNAL ;
    PORT
      LAYER M5 ;
        RECT  12.528 30.048 12.552 30.24 ;
    END
  END first[99]
  PIN first[9]
    DIRECTION OUTPUT ;
    USE SIGNAL ;
    PORT
      LAYER M5 ;
        RECT  3.888 30.048 3.912 30.24 ;
    END
  END first[9]
  PIN last[0]
    DIRECTION OUTPUT ;
    USE SIGNAL ;
    PORT
      LAYER M4 ;
        RECT  30.048 3.024 30.24 3.048 ;
    END
  END last[0]
  PIN last[100]
    DIRECTION OUTPUT ;
    USE SIGNAL ;
    PORT
      LAYER M4 ;
        RECT  30.048 12.624 30.24 12.648 ;
    END
  END last[100]
  PIN last[101]
    DIRECTION OUTPUT ;
    USE SIGNAL ;
    PORT
      LAYER M4 ;
        RECT  30.048 12.72 30.24 12.744 ;
    END
  END last[101]
  PIN last[102]
    DIRECTION OUTPUT ;
    USE SIGNAL ;
    PORT
      LAYER M4 ;
        RECT  30.048 12.816 30.24 12.84 ;
    END
  END last[102]
  PIN last[103]
    DIRECTION OUTPUT ;
    USE SIGNAL ;
    PORT
      LAYER M4 ;
        RECT  30.048 12.912 30.24 12.936 ;
    END
  END last[103]
  PIN last[104]
    DIRECTION OUTPUT ;
    USE SIGNAL ;
    PORT
      LAYER M4 ;
        RECT  30.048 13.008 30.24 13.032 ;
    END
  END last[104]
  PIN last[105]
    DIRECTION OUTPUT ;
    USE SIGNAL ;
    PORT
      LAYER M4 ;
        RECT  30.048 13.104 30.24 13.128 ;
    END
  END last[105]
  PIN last[106]
    DIRECTION OUTPUT ;
    USE SIGNAL ;
    PORT
      LAYER M4 ;
        RECT  30.048 13.2 30.24 13.224 ;
    END
  END last[106]
  PIN last[107]
    DIRECTION OUTPUT ;
    USE SIGNAL ;
    PORT
      LAYER M4 ;
        RECT  30.048 13.296 30.24 13.32 ;
    END
  END last[107]
  PIN last[108]
    DIRECTION OUTPUT ;
    USE SIGNAL ;
    PORT
      LAYER M4 ;
        RECT  30.048 13.392 30.24 13.416 ;
    END
  END last[108]
  PIN last[109]
    DIRECTION OUTPUT ;
    USE SIGNAL ;
    PORT
      LAYER M4 ;
        RECT  30.048 13.488 30.24 13.512 ;
    END
  END last[109]
  PIN last[10]
    DIRECTION OUTPUT ;
    USE SIGNAL ;
    PORT
      LAYER M4 ;
        RECT  30.048 3.984 30.24 4.008 ;
    END
  END last[10]
  PIN last[110]
    DIRECTION OUTPUT ;
    USE SIGNAL ;
    PORT
      LAYER M4 ;
        RECT  30.048 13.584 30.24 13.608 ;
    END
  END last[110]
  PIN last[111]
    DIRECTION OUTPUT ;
    USE SIGNAL ;
    PORT
      LAYER M4 ;
        RECT  30.048 13.68 30.24 13.704 ;
    END
  END last[111]
  PIN last[112]
    DIRECTION OUTPUT ;
    USE SIGNAL ;
    PORT
      LAYER M4 ;
        RECT  30.048 13.776 30.24 13.8 ;
    END
  END last[112]
  PIN last[113]
    DIRECTION OUTPUT ;
    USE SIGNAL ;
    PORT
      LAYER M4 ;
        RECT  30.048 13.872 30.24 13.896 ;
    END
  END last[113]
  PIN last[114]
    DIRECTION OUTPUT ;
    USE SIGNAL ;
    PORT
      LAYER M4 ;
        RECT  30.048 13.968 30.24 13.992 ;
    END
  END last[114]
  PIN last[115]
    DIRECTION OUTPUT ;
    USE SIGNAL ;
    PORT
      LAYER M4 ;
        RECT  30.048 14.064 30.24 14.088 ;
    END
  END last[115]
  PIN last[116]
    DIRECTION OUTPUT ;
    USE SIGNAL ;
    PORT
      LAYER M4 ;
        RECT  30.048 14.16 30.24 14.184 ;
    END
  END last[116]
  PIN last[117]
    DIRECTION OUTPUT ;
    USE SIGNAL ;
    PORT
      LAYER M4 ;
        RECT  30.048 14.256 30.24 14.28 ;
    END
  END last[117]
  PIN last[118]
    DIRECTION OUTPUT ;
    USE SIGNAL ;
    PORT
      LAYER M4 ;
        RECT  30.048 14.352 30.24 14.376 ;
    END
  END last[118]
  PIN last[119]
    DIRECTION OUTPUT ;
    USE SIGNAL ;
    PORT
      LAYER M4 ;
        RECT  30.048 14.448 30.24 14.472 ;
    END
  END last[119]
  PIN last[11]
    DIRECTION OUTPUT ;
    USE SIGNAL ;
    PORT
      LAYER M4 ;
        RECT  30.048 4.08 30.24 4.104 ;
    END
  END last[11]
  PIN last[120]
    DIRECTION OUTPUT ;
    USE SIGNAL ;
    PORT
      LAYER M4 ;
        RECT  30.048 14.544 30.24 14.568 ;
    END
  END last[120]
  PIN last[121]
    DIRECTION OUTPUT ;
    USE SIGNAL ;
    PORT
      LAYER M4 ;
        RECT  30.048 14.64 30.24 14.664 ;
    END
  END last[121]
  PIN last[122]
    DIRECTION OUTPUT ;
    USE SIGNAL ;
    PORT
      LAYER M4 ;
        RECT  30.048 14.736 30.24 14.76 ;
    END
  END last[122]
  PIN last[123]
    DIRECTION OUTPUT ;
    USE SIGNAL ;
    PORT
      LAYER M4 ;
        RECT  30.048 14.832 30.24 14.856 ;
    END
  END last[123]
  PIN last[124]
    DIRECTION OUTPUT ;
    USE SIGNAL ;
    PORT
      LAYER M4 ;
        RECT  30.048 14.928 30.24 14.952 ;
    END
  END last[124]
  PIN last[125]
    DIRECTION OUTPUT ;
    USE SIGNAL ;
    PORT
      LAYER M4 ;
        RECT  30.048 15.024 30.24 15.048 ;
    END
  END last[125]
  PIN last[126]
    DIRECTION OUTPUT ;
    USE SIGNAL ;
    PORT
      LAYER M4 ;
        RECT  30.048 15.12 30.24 15.144 ;
    END
  END last[126]
  PIN last[127]
    DIRECTION OUTPUT ;
    USE SIGNAL ;
    PORT
      LAYER M4 ;
        RECT  30.048 15.216 30.24 15.24 ;
    END
  END last[127]
  PIN last[12]
    DIRECTION OUTPUT ;
    USE SIGNAL ;
    PORT
      LAYER M4 ;
        RECT  30.048 4.176 30.24 4.2 ;
    END
  END last[12]
  PIN last[13]
    DIRECTION OUTPUT ;
    USE SIGNAL ;
    PORT
      LAYER M4 ;
        RECT  30.048 4.272 30.24 4.296 ;
    END
  END last[13]
  PIN last[14]
    DIRECTION OUTPUT ;
    USE SIGNAL ;
    PORT
      LAYER M4 ;
        RECT  30.048 4.368 30.24 4.392 ;
    END
  END last[14]
  PIN last[15]
    DIRECTION OUTPUT ;
    USE SIGNAL ;
    PORT
      LAYER M4 ;
        RECT  30.048 4.464 30.24 4.488 ;
    END
  END last[15]
  PIN last[16]
    DIRECTION OUTPUT ;
    USE SIGNAL ;
    PORT
      LAYER M4 ;
        RECT  30.048 4.56 30.24 4.584 ;
    END
  END last[16]
  PIN last[17]
    DIRECTION OUTPUT ;
    USE SIGNAL ;
    PORT
      LAYER M4 ;
        RECT  30.048 4.656 30.24 4.68 ;
    END
  END last[17]
  PIN last[18]
    DIRECTION OUTPUT ;
    USE SIGNAL ;
    PORT
      LAYER M4 ;
        RECT  30.048 4.752 30.24 4.776 ;
    END
  END last[18]
  PIN last[19]
    DIRECTION OUTPUT ;
    USE SIGNAL ;
    PORT
      LAYER M4 ;
        RECT  30.048 4.848 30.24 4.872 ;
    END
  END last[19]
  PIN last[1]
    DIRECTION OUTPUT ;
    USE SIGNAL ;
    PORT
      LAYER M4 ;
        RECT  30.048 3.12 30.24 3.144 ;
    END
  END last[1]
  PIN last[20]
    DIRECTION OUTPUT ;
    USE SIGNAL ;
    PORT
      LAYER M4 ;
        RECT  30.048 4.944 30.24 4.968 ;
    END
  END last[20]
  PIN last[21]
    DIRECTION OUTPUT ;
    USE SIGNAL ;
    PORT
      LAYER M4 ;
        RECT  30.048 5.04 30.24 5.064 ;
    END
  END last[21]
  PIN last[22]
    DIRECTION OUTPUT ;
    USE SIGNAL ;
    PORT
      LAYER M4 ;
        RECT  30.048 5.136 30.24 5.16 ;
    END
  END last[22]
  PIN last[23]
    DIRECTION OUTPUT ;
    USE SIGNAL ;
    PORT
      LAYER M4 ;
        RECT  30.048 5.232 30.24 5.256 ;
    END
  END last[23]
  PIN last[24]
    DIRECTION OUTPUT ;
    USE SIGNAL ;
    PORT
      LAYER M4 ;
        RECT  30.048 5.328 30.24 5.352 ;
    END
  END last[24]
  PIN last[25]
    DIRECTION OUTPUT ;
    USE SIGNAL ;
    PORT
      LAYER M4 ;
        RECT  30.048 5.424 30.24 5.448 ;
    END
  END last[25]
  PIN last[26]
    DIRECTION OUTPUT ;
    USE SIGNAL ;
    PORT
      LAYER M4 ;
        RECT  30.048 5.52 30.24 5.544 ;
    END
  END last[26]
  PIN last[27]
    DIRECTION OUTPUT ;
    USE SIGNAL ;
    PORT
      LAYER M4 ;
        RECT  30.048 5.616 30.24 5.64 ;
    END
  END last[27]
  PIN last[28]
    DIRECTION OUTPUT ;
    USE SIGNAL ;
    PORT
      LAYER M4 ;
        RECT  30.048 5.712 30.24 5.736 ;
    END
  END last[28]
  PIN last[29]
    DIRECTION OUTPUT ;
    USE SIGNAL ;
    PORT
      LAYER M4 ;
        RECT  30.048 5.808 30.24 5.832 ;
    END
  END last[29]
  PIN last[2]
    DIRECTION OUTPUT ;
    USE SIGNAL ;
    PORT
      LAYER M4 ;
        RECT  30.048 3.216 30.24 3.24 ;
    END
  END last[2]
  PIN last[30]
    DIRECTION OUTPUT ;
    USE SIGNAL ;
    PORT
      LAYER M4 ;
        RECT  30.048 5.904 30.24 5.928 ;
    END
  END last[30]
  PIN last[31]
    DIRECTION OUTPUT ;
    USE SIGNAL ;
    PORT
      LAYER M4 ;
        RECT  30.048 6 30.24 6.024 ;
    END
  END last[31]
  PIN last[32]
    DIRECTION OUTPUT ;
    USE SIGNAL ;
    PORT
      LAYER M4 ;
        RECT  30.048 6.096 30.24 6.12 ;
    END
  END last[32]
  PIN last[33]
    DIRECTION OUTPUT ;
    USE SIGNAL ;
    PORT
      LAYER M4 ;
        RECT  30.048 6.192 30.24 6.216 ;
    END
  END last[33]
  PIN last[34]
    DIRECTION OUTPUT ;
    USE SIGNAL ;
    PORT
      LAYER M4 ;
        RECT  30.048 6.288 30.24 6.312 ;
    END
  END last[34]
  PIN last[35]
    DIRECTION OUTPUT ;
    USE SIGNAL ;
    PORT
      LAYER M4 ;
        RECT  30.048 6.384 30.24 6.408 ;
    END
  END last[35]
  PIN last[36]
    DIRECTION OUTPUT ;
    USE SIGNAL ;
    PORT
      LAYER M4 ;
        RECT  30.048 6.48 30.24 6.504 ;
    END
  END last[36]
  PIN last[37]
    DIRECTION OUTPUT ;
    USE SIGNAL ;
    PORT
      LAYER M4 ;
        RECT  30.048 6.576 30.24 6.6 ;
    END
  END last[37]
  PIN last[38]
    DIRECTION OUTPUT ;
    USE SIGNAL ;
    PORT
      LAYER M4 ;
        RECT  30.048 6.672 30.24 6.696 ;
    END
  END last[38]
  PIN last[39]
    DIRECTION OUTPUT ;
    USE SIGNAL ;
    PORT
      LAYER M4 ;
        RECT  30.048 6.768 30.24 6.792 ;
    END
  END last[39]
  PIN last[3]
    DIRECTION OUTPUT ;
    USE SIGNAL ;
    PORT
      LAYER M4 ;
        RECT  30.048 3.312 30.24 3.336 ;
    END
  END last[3]
  PIN last[40]
    DIRECTION OUTPUT ;
    USE SIGNAL ;
    PORT
      LAYER M4 ;
        RECT  30.048 6.864 30.24 6.888 ;
    END
  END last[40]
  PIN last[41]
    DIRECTION OUTPUT ;
    USE SIGNAL ;
    PORT
      LAYER M4 ;
        RECT  30.048 6.96 30.24 6.984 ;
    END
  END last[41]
  PIN last[42]
    DIRECTION OUTPUT ;
    USE SIGNAL ;
    PORT
      LAYER M4 ;
        RECT  30.048 7.056 30.24 7.08 ;
    END
  END last[42]
  PIN last[43]
    DIRECTION OUTPUT ;
    USE SIGNAL ;
    PORT
      LAYER M4 ;
        RECT  30.048 7.152 30.24 7.176 ;
    END
  END last[43]
  PIN last[44]
    DIRECTION OUTPUT ;
    USE SIGNAL ;
    PORT
      LAYER M4 ;
        RECT  30.048 7.248 30.24 7.272 ;
    END
  END last[44]
  PIN last[45]
    DIRECTION OUTPUT ;
    USE SIGNAL ;
    PORT
      LAYER M4 ;
        RECT  30.048 7.344 30.24 7.368 ;
    END
  END last[45]
  PIN last[46]
    DIRECTION OUTPUT ;
    USE SIGNAL ;
    PORT
      LAYER M4 ;
        RECT  30.048 7.44 30.24 7.464 ;
    END
  END last[46]
  PIN last[47]
    DIRECTION OUTPUT ;
    USE SIGNAL ;
    PORT
      LAYER M4 ;
        RECT  30.048 7.536 30.24 7.56 ;
    END
  END last[47]
  PIN last[48]
    DIRECTION OUTPUT ;
    USE SIGNAL ;
    PORT
      LAYER M4 ;
        RECT  30.048 7.632 30.24 7.656 ;
    END
  END last[48]
  PIN last[49]
    DIRECTION OUTPUT ;
    USE SIGNAL ;
    PORT
      LAYER M4 ;
        RECT  30.048 7.728 30.24 7.752 ;
    END
  END last[49]
  PIN last[4]
    DIRECTION OUTPUT ;
    USE SIGNAL ;
    PORT
      LAYER M4 ;
        RECT  30.048 3.408 30.24 3.432 ;
    END
  END last[4]
  PIN last[50]
    DIRECTION OUTPUT ;
    USE SIGNAL ;
    PORT
      LAYER M4 ;
        RECT  30.048 7.824 30.24 7.848 ;
    END
  END last[50]
  PIN last[51]
    DIRECTION OUTPUT ;
    USE SIGNAL ;
    PORT
      LAYER M4 ;
        RECT  30.048 7.92 30.24 7.944 ;
    END
  END last[51]
  PIN last[52]
    DIRECTION OUTPUT ;
    USE SIGNAL ;
    PORT
      LAYER M4 ;
        RECT  30.048 8.016 30.24 8.04 ;
    END
  END last[52]
  PIN last[53]
    DIRECTION OUTPUT ;
    USE SIGNAL ;
    PORT
      LAYER M4 ;
        RECT  30.048 8.112 30.24 8.136 ;
    END
  END last[53]
  PIN last[54]
    DIRECTION OUTPUT ;
    USE SIGNAL ;
    PORT
      LAYER M4 ;
        RECT  30.048 8.208 30.24 8.232 ;
    END
  END last[54]
  PIN last[55]
    DIRECTION OUTPUT ;
    USE SIGNAL ;
    PORT
      LAYER M4 ;
        RECT  30.048 8.304 30.24 8.328 ;
    END
  END last[55]
  PIN last[56]
    DIRECTION OUTPUT ;
    USE SIGNAL ;
    PORT
      LAYER M4 ;
        RECT  30.048 8.4 30.24 8.424 ;
    END
  END last[56]
  PIN last[57]
    DIRECTION OUTPUT ;
    USE SIGNAL ;
    PORT
      LAYER M4 ;
        RECT  30.048 8.496 30.24 8.52 ;
    END
  END last[57]
  PIN last[58]
    DIRECTION OUTPUT ;
    USE SIGNAL ;
    PORT
      LAYER M4 ;
        RECT  30.048 8.592 30.24 8.616 ;
    END
  END last[58]
  PIN last[59]
    DIRECTION OUTPUT ;
    USE SIGNAL ;
    PORT
      LAYER M4 ;
        RECT  30.048 8.688 30.24 8.712 ;
    END
  END last[59]
  PIN last[5]
    DIRECTION OUTPUT ;
    USE SIGNAL ;
    PORT
      LAYER M4 ;
        RECT  30.048 3.504 30.24 3.528 ;
    END
  END last[5]
  PIN last[60]
    DIRECTION OUTPUT ;
    USE SIGNAL ;
    PORT
      LAYER M4 ;
        RECT  30.048 8.784 30.24 8.808 ;
    END
  END last[60]
  PIN last[61]
    DIRECTION OUTPUT ;
    USE SIGNAL ;
    PORT
      LAYER M4 ;
        RECT  30.048 8.88 30.24 8.904 ;
    END
  END last[61]
  PIN last[62]
    DIRECTION OUTPUT ;
    USE SIGNAL ;
    PORT
      LAYER M4 ;
        RECT  30.048 8.976 30.24 9 ;
    END
  END last[62]
  PIN last[63]
    DIRECTION OUTPUT ;
    USE SIGNAL ;
    PORT
      LAYER M4 ;
        RECT  30.048 9.072 30.24 9.096 ;
    END
  END last[63]
  PIN last[64]
    DIRECTION OUTPUT ;
    USE SIGNAL ;
    PORT
      LAYER M4 ;
        RECT  30.048 9.168 30.24 9.192 ;
    END
  END last[64]
  PIN last[65]
    DIRECTION OUTPUT ;
    USE SIGNAL ;
    PORT
      LAYER M4 ;
        RECT  30.048 9.264 30.24 9.288 ;
    END
  END last[65]
  PIN last[66]
    DIRECTION OUTPUT ;
    USE SIGNAL ;
    PORT
      LAYER M4 ;
        RECT  30.048 9.36 30.24 9.384 ;
    END
  END last[66]
  PIN last[67]
    DIRECTION OUTPUT ;
    USE SIGNAL ;
    PORT
      LAYER M4 ;
        RECT  30.048 9.456 30.24 9.48 ;
    END
  END last[67]
  PIN last[68]
    DIRECTION OUTPUT ;
    USE SIGNAL ;
    PORT
      LAYER M4 ;
        RECT  30.048 9.552 30.24 9.576 ;
    END
  END last[68]
  PIN last[69]
    DIRECTION OUTPUT ;
    USE SIGNAL ;
    PORT
      LAYER M4 ;
        RECT  30.048 9.648 30.24 9.672 ;
    END
  END last[69]
  PIN last[6]
    DIRECTION OUTPUT ;
    USE SIGNAL ;
    PORT
      LAYER M4 ;
        RECT  30.048 3.6 30.24 3.624 ;
    END
  END last[6]
  PIN last[70]
    DIRECTION OUTPUT ;
    USE SIGNAL ;
    PORT
      LAYER M4 ;
        RECT  30.048 9.744 30.24 9.768 ;
    END
  END last[70]
  PIN last[71]
    DIRECTION OUTPUT ;
    USE SIGNAL ;
    PORT
      LAYER M4 ;
        RECT  30.048 9.84 30.24 9.864 ;
    END
  END last[71]
  PIN last[72]
    DIRECTION OUTPUT ;
    USE SIGNAL ;
    PORT
      LAYER M4 ;
        RECT  30.048 9.936 30.24 9.96 ;
    END
  END last[72]
  PIN last[73]
    DIRECTION OUTPUT ;
    USE SIGNAL ;
    PORT
      LAYER M4 ;
        RECT  30.048 10.032 30.24 10.056 ;
    END
  END last[73]
  PIN last[74]
    DIRECTION OUTPUT ;
    USE SIGNAL ;
    PORT
      LAYER M4 ;
        RECT  30.048 10.128 30.24 10.152 ;
    END
  END last[74]
  PIN last[75]
    DIRECTION OUTPUT ;
    USE SIGNAL ;
    PORT
      LAYER M4 ;
        RECT  30.048 10.224 30.24 10.248 ;
    END
  END last[75]
  PIN last[76]
    DIRECTION OUTPUT ;
    USE SIGNAL ;
    PORT
      LAYER M4 ;
        RECT  30.048 10.32 30.24 10.344 ;
    END
  END last[76]
  PIN last[77]
    DIRECTION OUTPUT ;
    USE SIGNAL ;
    PORT
      LAYER M4 ;
        RECT  30.048 10.416 30.24 10.44 ;
    END
  END last[77]
  PIN last[78]
    DIRECTION OUTPUT ;
    USE SIGNAL ;
    PORT
      LAYER M4 ;
        RECT  30.048 10.512 30.24 10.536 ;
    END
  END last[78]
  PIN last[79]
    DIRECTION OUTPUT ;
    USE SIGNAL ;
    PORT
      LAYER M4 ;
        RECT  30.048 10.608 30.24 10.632 ;
    END
  END last[79]
  PIN last[7]
    DIRECTION OUTPUT ;
    USE SIGNAL ;
    PORT
      LAYER M4 ;
        RECT  30.048 3.696 30.24 3.72 ;
    END
  END last[7]
  PIN last[80]
    DIRECTION OUTPUT ;
    USE SIGNAL ;
    PORT
      LAYER M4 ;
        RECT  30.048 10.704 30.24 10.728 ;
    END
  END last[80]
  PIN last[81]
    DIRECTION OUTPUT ;
    USE SIGNAL ;
    PORT
      LAYER M4 ;
        RECT  30.048 10.8 30.24 10.824 ;
    END
  END last[81]
  PIN last[82]
    DIRECTION OUTPUT ;
    USE SIGNAL ;
    PORT
      LAYER M4 ;
        RECT  30.048 10.896 30.24 10.92 ;
    END
  END last[82]
  PIN last[83]
    DIRECTION OUTPUT ;
    USE SIGNAL ;
    PORT
      LAYER M4 ;
        RECT  30.048 10.992 30.24 11.016 ;
    END
  END last[83]
  PIN last[84]
    DIRECTION OUTPUT ;
    USE SIGNAL ;
    PORT
      LAYER M4 ;
        RECT  30.048 11.088 30.24 11.112 ;
    END
  END last[84]
  PIN last[85]
    DIRECTION OUTPUT ;
    USE SIGNAL ;
    PORT
      LAYER M4 ;
        RECT  30.048 11.184 30.24 11.208 ;
    END
  END last[85]
  PIN last[86]
    DIRECTION OUTPUT ;
    USE SIGNAL ;
    PORT
      LAYER M4 ;
        RECT  30.048 11.28 30.24 11.304 ;
    END
  END last[86]
  PIN last[87]
    DIRECTION OUTPUT ;
    USE SIGNAL ;
    PORT
      LAYER M4 ;
        RECT  30.048 11.376 30.24 11.4 ;
    END
  END last[87]
  PIN last[88]
    DIRECTION OUTPUT ;
    USE SIGNAL ;
    PORT
      LAYER M4 ;
        RECT  30.048 11.472 30.24 11.496 ;
    END
  END last[88]
  PIN last[89]
    DIRECTION OUTPUT ;
    USE SIGNAL ;
    PORT
      LAYER M4 ;
        RECT  30.048 11.568 30.24 11.592 ;
    END
  END last[89]
  PIN last[8]
    DIRECTION OUTPUT ;
    USE SIGNAL ;
    PORT
      LAYER M4 ;
        RECT  30.048 3.792 30.24 3.816 ;
    END
  END last[8]
  PIN last[90]
    DIRECTION OUTPUT ;
    USE SIGNAL ;
    PORT
      LAYER M4 ;
        RECT  30.048 11.664 30.24 11.688 ;
    END
  END last[90]
  PIN last[91]
    DIRECTION OUTPUT ;
    USE SIGNAL ;
    PORT
      LAYER M4 ;
        RECT  30.048 11.76 30.24 11.784 ;
    END
  END last[91]
  PIN last[92]
    DIRECTION OUTPUT ;
    USE SIGNAL ;
    PORT
      LAYER M4 ;
        RECT  30.048 11.856 30.24 11.88 ;
    END
  END last[92]
  PIN last[93]
    DIRECTION OUTPUT ;
    USE SIGNAL ;
    PORT
      LAYER M4 ;
        RECT  30.048 11.952 30.24 11.976 ;
    END
  END last[93]
  PIN last[94]
    DIRECTION OUTPUT ;
    USE SIGNAL ;
    PORT
      LAYER M4 ;
        RECT  30.048 12.048 30.24 12.072 ;
    END
  END last[94]
  PIN last[95]
    DIRECTION OUTPUT ;
    USE SIGNAL ;
    PORT
      LAYER M4 ;
        RECT  30.048 12.144 30.24 12.168 ;
    END
  END last[95]
  PIN last[96]
    DIRECTION OUTPUT ;
    USE SIGNAL ;
    PORT
      LAYER M4 ;
        RECT  30.048 12.24 30.24 12.264 ;
    END
  END last[96]
  PIN last[97]
    DIRECTION OUTPUT ;
    USE SIGNAL ;
    PORT
      LAYER M4 ;
        RECT  30.048 12.336 30.24 12.36 ;
    END
  END last[97]
  PIN last[98]
    DIRECTION OUTPUT ;
    USE SIGNAL ;
    PORT
      LAYER M4 ;
        RECT  30.048 12.432 30.24 12.456 ;
    END
  END last[98]
  PIN last[99]
    DIRECTION OUTPUT ;
    USE SIGNAL ;
    PORT
      LAYER M4 ;
        RECT  30.048 12.528 30.24 12.552 ;
    END
  END last[99]
  PIN last[9]
    DIRECTION OUTPUT ;
    USE SIGNAL ;
    PORT
      LAYER M4 ;
        RECT  30.048 3.888 30.24 3.912 ;
    END
  END last[9]
  PIN rst_a
    DIRECTION INPUT ;
    USE SIGNAL ;
    PORT
      LAYER M5 ;
        RECT  1.488 30.048 1.512 30.24 ;
    END
  END rst_a
  PIN VDD
    DIRECTION INOUT ;
    USE POWER ;
    PORT
      LAYER M5 ;
        RECT  24.192 2.151 24.312 28.089 ;
        RECT  18.792 2.151 18.912 28.089 ;
        RECT  13.392 2.151 13.512 28.089 ;
        RECT  7.992 2.151 8.112 28.089 ;
        RECT  2.592 2.151 2.712 28.089 ;
    END
  END VDD
  PIN VSS
    DIRECTION INOUT ;
    USE GROUND ;
    PORT
      LAYER M5 ;
        RECT  24 2.137 24.12 28.103 ;
        RECT  18.6 2.137 18.72 28.103 ;
        RECT  13.2 2.137 13.32 28.103 ;
        RECT  7.8 2.137 7.92 28.103 ;
        RECT  2.4 2.137 2.52 28.103 ;
    END
  END VSS
  # OT_OBS_CLOSED layer=M5 d_um=1.536 added=21
  OBS
    LAYER RVTN ;
     RECT  2.16 2.16 28.08 2.295 ;
     RECT  2.16 2.565 28.08 2.835 ;
     RECT  2.16 3.105 28.08 3.375 ;
     RECT  2.16 3.645 28.08 3.915 ;
     RECT  2.16 4.185 28.08 4.455 ;
     RECT  2.16 4.725 28.08 4.995 ;
     RECT  2.16 5.265 28.08 5.535 ;
     RECT  2.16 5.805 28.08 6.075 ;
     RECT  2.16 6.345 28.08 6.615 ;
     RECT  2.16 6.885 28.08 7.155 ;
     RECT  2.16 7.425 28.08 7.695 ;
     RECT  2.16 7.965 28.08 8.235 ;
     RECT  2.16 8.505 28.08 8.775 ;
     RECT  2.16 9.045 28.08 9.315 ;
     RECT  2.16 9.585 28.08 9.855 ;
     RECT  2.16 10.125 28.08 10.395 ;
     RECT  2.16 10.665 28.08 10.935 ;
     RECT  2.16 11.205 28.08 11.475 ;
     RECT  2.16 11.745 28.08 12.015 ;
     RECT  2.16 12.285 28.08 12.555 ;
     RECT  2.16 12.825 28.08 13.095 ;
     RECT  2.16 13.365 28.08 13.635 ;
     RECT  2.16 13.905 28.08 14.175 ;
     RECT  2.16 14.445 28.08 14.715 ;
     RECT  2.16 14.985 28.08 15.255 ;
     RECT  2.16 15.525 28.08 15.795 ;
     RECT  2.16 16.065 28.08 16.335 ;
     RECT  2.16 16.605 28.08 16.875 ;
     RECT  2.16 17.145 28.08 17.415 ;
     RECT  2.16 17.685 28.08 17.955 ;
     RECT  2.16 18.225 28.08 18.495 ;
     RECT  2.16 18.765 28.08 19.035 ;
     RECT  2.16 19.305 28.08 19.575 ;
     RECT  2.16 19.845 28.08 20.115 ;
     RECT  2.16 20.385 28.08 20.655 ;
     RECT  2.16 20.925 28.08 21.195 ;
     RECT  2.16 21.465 28.08 21.735 ;
     RECT  2.16 22.005 28.08 22.275 ;
     RECT  2.16 22.545 28.08 22.815 ;
     RECT  2.16 23.085 28.08 23.355 ;
     RECT  2.16 23.625 28.08 23.895 ;
     RECT  2.16 24.165 28.08 24.435 ;
     RECT  2.16 24.705 28.08 24.975 ;
     RECT  2.16 25.245 28.08 25.515 ;
     RECT  2.16 25.785 28.08 26.055 ;
     RECT  2.16 26.325 28.08 26.595 ;
     RECT  2.16 26.865 28.08 27.135 ;
     RECT  2.16 27.405 28.08 27.675 ;
     RECT  2.16 27.945 28.08 28.08 ;
    LAYER RVTP ;
     RECT  2.16 2.295 28.08 2.565 ;
     RECT  2.16 2.835 28.08 3.105 ;
     RECT  2.16 3.375 28.08 3.645 ;
     RECT  2.16 3.915 28.08 4.185 ;
     RECT  2.16 4.455 28.08 4.725 ;
     RECT  2.16 4.995 28.08 5.265 ;
     RECT  2.16 5.535 28.08 5.805 ;
     RECT  2.16 6.075 28.08 6.345 ;
     RECT  2.16 6.615 28.08 6.885 ;
     RECT  2.16 7.155 28.08 7.425 ;
     RECT  2.16 7.695 28.08 7.965 ;
     RECT  2.16 8.235 28.08 8.505 ;
     RECT  2.16 8.775 28.08 9.045 ;
     RECT  2.16 9.315 28.08 9.585 ;
     RECT  2.16 9.855 28.08 10.125 ;
     RECT  2.16 10.395 28.08 10.665 ;
     RECT  2.16 10.935 28.08 11.205 ;
     RECT  2.16 11.475 28.08 11.745 ;
     RECT  2.16 12.015 28.08 12.285 ;
     RECT  2.16 12.555 28.08 12.825 ;
     RECT  2.16 13.095 28.08 13.365 ;
     RECT  2.16 13.635 28.08 13.905 ;
     RECT  2.16 14.175 28.08 14.445 ;
     RECT  2.16 14.715 28.08 14.985 ;
     RECT  2.16 15.255 28.08 15.525 ;
     RECT  2.16 15.795 28.08 16.065 ;
     RECT  2.16 16.335 28.08 16.605 ;
     RECT  2.16 16.875 28.08 17.145 ;
     RECT  2.16 17.415 28.08 17.685 ;
     RECT  2.16 17.955 28.08 18.225 ;
     RECT  2.16 18.495 28.08 18.765 ;
     RECT  2.16 19.035 28.08 19.305 ;
     RECT  2.16 19.575 28.08 19.845 ;
     RECT  2.16 20.115 28.08 20.385 ;
     RECT  2.16 20.655 28.08 20.925 ;
     RECT  2.16 21.195 28.08 21.465 ;
     RECT  2.16 21.735 28.08 22.005 ;
     RECT  2.16 22.275 28.08 22.545 ;
     RECT  2.16 22.815 28.08 23.085 ;
     RECT  2.16 23.355 28.08 23.625 ;
     RECT  2.16 23.895 28.08 24.165 ;
     RECT  2.16 24.435 28.08 24.705 ;
     RECT  2.16 24.975 28.08 25.245 ;
     RECT  2.16 25.515 28.08 25.785 ;
     RECT  2.16 26.055 28.08 26.325 ;
     RECT  2.16 26.595 28.08 26.865 ;
     RECT  2.16 27.135 28.08 27.405 ;
     RECT  2.16 27.675 28.08 27.945 ;
    LAYER M1 ;
     RECT  2.16 2.151 28.08 28.089 ;
    LAYER M2 ;
     RECT  0.211 2.232 0.247 2.25 ;
     RECT  0.211 3.384 0.247 3.402 ;
     RECT  0.211 5.58 0.247 5.598 ;
     RECT  0.211 13.608 0.347 13.626 ;
     RECT  0.247 5.58 0.463 5.76 ;
     RECT  0.247 2.232 0.535 3.402 ;
     RECT  0.211 4.392 0.535 4.41 ;
     RECT  0.535 2.232 2.16 4.518 ;
     RECT  0.463 5.346 2.16 5.76 ;
     RECT  0.535 6.696 2.16 6.714 ;
     RECT  0.211 7.902 2.16 7.92 ;
     RECT  0.535 9.09 2.16 9.108 ;
     RECT  1.687 15.57 2.16 15.588 ;
     RECT  1.723 16.812 2.16 16.83 ;
     RECT  2.16 2.151 19.363 28.089 ;
     RECT  19.363 2.106 22.819 28.089 ;
     RECT  22.819 1.962 26.735 28.089 ;
     RECT  26.735 2.106 28.08 28.089 ;
     RECT  28.08 2.106 28.103 19.224 ;
     RECT  28.103 15.156 28.499 17.874 ;
     RECT  28.103 18.666 28.535 19.224 ;
     RECT  28.499 15.156 28.859 17.604 ;
     RECT  28.859 15.156 28.895 16.524 ;
     RECT  28.895 15.156 28.967 16.434 ;
     RECT  28.103 2.106 29.111 14.004 ;
     RECT  29.111 2.106 29.147 2.754 ;
     RECT  29.111 6.696 29.147 9.648 ;
     RECT  29.111 13.914 29.147 14.004 ;
     RECT  29.147 6.966 29.219 9.648 ;
     RECT  28.535 19.206 29.399 19.224 ;
     RECT  28.967 15.156 29.435 16.164 ;
     RECT  29.111 10.944 29.615 13.014 ;
     RECT  29.219 7.164 29.651 9.648 ;
     RECT  29.615 10.944 29.651 12.924 ;
     RECT  29.147 2.106 29.687 2.664 ;
     RECT  29.111 3.654 29.687 5.832 ;
     RECT  29.651 7.164 29.687 7.722 ;
     RECT  29.651 8.586 29.687 9.648 ;
     RECT  29.651 10.944 29.687 12.312 ;
     RECT  29.687 2.106 29.723 2.556 ;
     RECT  29.687 3.654 29.723 5.292 ;
     RECT  29.687 7.164 29.723 7.182 ;
     RECT  29.687 9.054 29.723 9.648 ;
     RECT  29.687 11.952 29.723 12.312 ;
     RECT  29.435 15.156 29.723 16.092 ;
     RECT  29.723 15.156 29.731 15.174 ;
     RECT  29.723 2.538 29.759 2.556 ;
     RECT  29.723 4.806 29.759 4.824 ;
     RECT  29.687 10.944 29.759 10.962 ;
     RECT  29.723 11.952 29.759 11.97 ;
     RECT  29.147 13.914 29.759 13.932 ;
     RECT  29.731 14.796 29.759 15.174 ;
     RECT  29.723 3.654 29.795 3.834 ;
     RECT  29.795 3.654 29.831 3.672 ;
     RECT  29.759 14.796 29.831 14.814 ;
     RECT  29.723 16.074 29.975 16.092 ;
     RECT  28.859 17.586 30.047 17.604 ;
     RECT  30.019 6.201 30.119 6.219 ;
    LAYER M3 ;
     RECT  26.712 1.957 26.73 2.029 ;
     RECT  24.66 2.029 24.678 2.101 ;
     RECT  26.1 2.029 26.73 2.101 ;
     RECT  19.368 2.101 19.386 2.143 ;
     RECT  24.66 2.101 26.73 2.143 ;
     RECT  24.015 2.143 26.73 2.191 ;
     RECT  22.824 1.957 22.842 2.263 ;
     RECT  24.015 2.191 26.946 2.263 ;
     RECT  27.72 2.191 27.738 2.263 ;
     RECT  2.415 2.143 2.505 2.371 ;
     RECT  2.415 2.371 2.574 2.413 ;
     RECT  7.815 2.143 7.905 2.413 ;
     RECT  13.215 2.143 13.305 2.413 ;
     RECT  2.415 2.413 2.697 2.461 ;
     RECT  18.615 2.143 19.386 2.461 ;
     RECT  22.356 2.263 22.842 2.461 ;
     RECT  24.015 2.263 27.954 2.461 ;
     RECT  29.7 2.101 29.718 2.533 ;
     RECT  18.615 2.461 19.926 2.569 ;
     RECT  29.7 2.533 29.754 2.605 ;
     RECT  18.576 2.569 19.926 2.606 ;
     RECT  29.34 2.605 29.754 2.731 ;
     RECT  5.04 2.641 5.13 2.759 ;
     RECT  0.216 2.227 0.234 2.767 ;
     RECT  22.356 2.461 27.954 2.767 ;
     RECT  5.04 2.759 5.058 2.831 ;
     RECT  29.124 2.731 29.754 2.875 ;
     RECT  21.6 2.767 27.954 2.911 ;
     RECT  18.576 2.606 19.89 3.029 ;
     RECT  21.456 2.911 27.954 3.109 ;
     RECT  29.124 2.875 29.826 3.109 ;
     RECT  0.216 2.767 0.27 3.145 ;
     RECT  21.384 3.109 27.954 3.209 ;
     RECT  17.244 3.181 17.262 3.299 ;
     RECT  21.384 3.209 21.69 3.299 ;
     RECT  2.415 2.461 3.906 3.307 ;
     RECT  22.5 3.209 27.954 3.341 ;
     RECT  29.088 3.109 29.826 3.343 ;
     RECT  19.692 3.029 19.89 3.451 ;
     RECT  2.34 3.307 3.906 3.499 ;
     RECT  21.384 3.299 21.654 3.569 ;
     RECT  19.692 3.451 19.962 3.721 ;
     RECT  2.304 3.499 3.906 3.811 ;
     RECT  19.692 3.721 20.034 3.811 ;
     RECT  21.384 3.569 21.474 3.811 ;
     RECT  2.304 3.811 4.338 3.883 ;
     RECT  28.512 3.343 29.826 3.917 ;
     RECT  0.216 3.145 0.306 3.955 ;
     RECT  19.692 3.811 21.474 3.965 ;
     RECT  14.832 3.109 14.85 3.983 ;
     RECT  18.576 3.029 18.954 3.991 ;
     RECT  19.692 3.965 20.07 3.991 ;
     RECT  22.5 3.341 27.666 3.991 ;
     RECT  16.524 3.343 16.542 4.081 ;
     RECT  17.64 3.403 17.658 4.081 ;
     RECT  16.524 4.081 17.658 4.109 ;
     RECT  18.576 3.991 20.07 4.181 ;
     RECT  2.304 3.883 4.41 4.225 ;
     RECT  6.804 3.811 6.822 4.225 ;
     RECT  17.028 4.109 17.658 4.261 ;
     RECT  18.576 4.181 20.034 4.261 ;
     RECT  17.028 4.261 20.034 4.289 ;
     RECT  2.268 4.225 4.842 4.351 ;
     RECT  20.952 3.965 21.474 4.379 ;
     RECT  2.268 4.351 4.914 4.397 ;
     RECT  17.1 4.289 20.034 4.415 ;
     RECT  6.588 4.225 6.822 4.451 ;
     RECT  6.66 4.451 6.822 4.487 ;
     RECT  22.428 3.991 27.666 4.531 ;
     RECT  6.732 4.487 6.822 4.559 ;
     RECT  22.428 4.531 27.738 4.657 ;
     RECT  28.512 3.917 29.79 4.657 ;
     RECT  0.216 3.955 0.558 4.685 ;
     RECT  2.304 4.397 4.914 4.693 ;
     RECT  22.428 4.657 29.79 4.781 ;
     RECT  2.304 4.693 5.202 4.801 ;
     RECT  21.096 4.379 21.474 4.801 ;
     RECT  22.428 4.781 29.754 4.801 ;
     RECT  21.096 4.801 29.754 4.829 ;
     RECT  14.832 4.801 14.85 4.963 ;
     RECT  21.24 4.829 29.754 4.973 ;
     RECT  17.64 4.415 20.034 5.269 ;
     RECT  2.304 4.801 5.814 5.305 ;
     RECT  17.172 5.269 20.034 5.419 ;
     RECT  6.804 4.559 6.822 5.431 ;
     RECT  14.832 4.963 14.922 5.431 ;
     RECT  17.1 5.419 20.034 5.431 ;
     RECT  0.468 4.685 0.558 5.575 ;
     RECT  17.1 5.431 20.43 5.639 ;
     RECT  0.216 5.575 0.558 5.645 ;
     RECT  17.1 5.639 20.178 5.693 ;
     RECT  17.1 5.693 19.674 5.707 ;
     RECT  0.216 5.645 0.522 5.741 ;
     RECT  21.24 4.973 27.954 5.773 ;
     RECT  2.268 5.305 5.814 5.845 ;
     RECT  6.552 5.431 6.822 5.845 ;
     RECT  14.832 5.431 14.958 5.845 ;
     RECT  2.268 5.845 6.822 5.933 ;
     RECT  14.832 5.845 14.994 5.999 ;
     RECT  2.304 5.933 6.822 6.043 ;
     RECT  14.976 5.999 14.994 6.071 ;
     RECT  2.304 6.043 6.894 6.143 ;
     RECT  16.56 5.707 19.674 6.143 ;
     RECT  29.088 4.973 29.754 6.187 ;
     RECT  29.088 6.187 30.042 6.196 ;
     RECT  29.088 6.196 30.114 6.269 ;
     RECT  16.56 6.143 19.602 6.283 ;
     RECT  20.916 5.773 27.954 6.385 ;
     RECT  20.52 6.385 27.954 6.421 ;
     RECT  16.452 6.283 19.602 6.539 ;
     RECT  16.452 6.539 17.694 6.575 ;
     RECT  20.376 6.421 27.954 6.655 ;
     RECT  29.088 6.269 29.682 6.655 ;
     RECT  0.252 5.741 0.522 6.691 ;
     RECT  0.252 6.691 0.558 6.797 ;
     RECT  20.376 6.655 29.682 6.797 ;
     RECT  17.028 6.575 17.694 6.845 ;
     RECT  18.615 6.539 19.602 6.845 ;
     RECT  0.54 6.797 0.558 6.893 ;
     RECT  7.815 2.413 8.097 6.961 ;
     RECT  2.304 6.143 6.822 7.051 ;
     RECT  20.376 6.797 27.954 7.079 ;
     RECT  20.376 7.079 21.942 7.123 ;
     RECT  29.052 6.797 29.682 7.159 ;
     RECT  2.268 7.051 6.822 7.321 ;
     RECT  2.268 7.321 6.858 7.429 ;
     RECT  7.632 6.961 8.097 7.429 ;
     RECT  14.976 7.465 14.994 7.501 ;
     RECT  29.052 7.159 29.718 7.565 ;
     RECT  17.1 6.845 17.694 7.591 ;
     RECT  18.615 6.845 18.897 7.591 ;
     RECT  14.904 7.501 15.03 7.627 ;
     RECT  22.716 7.079 27.954 7.627 ;
     RECT  14.868 7.627 15.03 7.661 ;
     RECT  14.868 7.661 14.994 7.723 ;
     RECT  14.832 7.723 14.994 7.757 ;
     RECT  16.56 7.591 18.897 7.771 ;
     RECT  19.728 7.123 21.942 7.771 ;
     RECT  14.832 7.757 14.922 7.799 ;
     RECT  16.56 7.771 21.942 7.889 ;
     RECT  16.56 7.889 21.762 7.901 ;
     RECT  2.268 7.429 8.097 7.915 ;
     RECT  2.232 7.915 8.097 8.005 ;
     RECT  8.82 7.969 8.838 8.005 ;
     RECT  2.232 8.005 8.838 8.033 ;
     RECT  22.716 7.627 27.99 8.041 ;
     RECT  16.56 7.901 19.386 8.107 ;
     RECT  16.308 8.107 19.386 8.159 ;
     RECT  0.216 7.897 0.234 8.237 ;
     RECT  20.232 7.901 21.762 8.267 ;
     RECT  16.56 8.159 19.386 8.303 ;
     RECT  20.232 8.267 21.582 8.381 ;
     RECT  22.536 8.041 27.99 8.395 ;
     RECT  29.052 7.565 29.682 8.395 ;
     RECT  20.232 8.381 20.574 8.429 ;
     RECT  21.348 8.381 21.582 8.429 ;
     RECT  1.152 8.299 1.17 8.477 ;
     RECT  14.832 7.799 14.85 8.545 ;
     RECT  2.268 8.033 8.838 8.807 ;
     RECT  22.536 8.395 29.682 8.815 ;
     RECT  2.304 8.807 8.838 8.851 ;
     RECT  14.832 8.545 14.886 8.879 ;
     RECT  22.464 8.815 29.682 9.049 ;
     RECT  21.492 8.429 21.582 9.085 ;
     RECT  22.464 9.049 29.718 9.085 ;
     RECT  21.492 9.085 29.718 9.101 ;
     RECT  16.56 8.303 19.206 9.113 ;
     RECT  17.928 9.113 19.206 9.121 ;
     RECT  0.54 9.085 0.558 9.197 ;
     RECT  16.56 9.113 17.154 9.275 ;
     RECT  2.304 8.851 9.018 9.283 ;
     RECT  2.304 9.283 9.198 9.481 ;
     RECT  2.304 9.481 9.234 9.517 ;
     RECT  17.928 9.121 19.494 9.517 ;
     RECT  14.868 8.879 14.886 9.617 ;
     RECT  21.492 9.101 28.674 9.643 ;
     RECT  17.928 9.517 19.566 9.653 ;
     RECT  29.628 9.101 29.718 9.653 ;
     RECT  20.988 9.643 28.674 9.661 ;
     RECT  2.304 9.517 9.45 9.739 ;
     RECT  20.52 9.661 28.674 9.781 ;
     RECT  2.268 9.739 9.45 9.787 ;
     RECT  2.268 9.787 9.774 9.823 ;
     RECT  10.764 9.751 10.782 9.823 ;
     RECT  14.832 9.751 14.85 9.851 ;
     RECT  16.56 9.275 16.794 9.923 ;
     RECT  19.62 9.781 28.674 9.925 ;
     RECT  17.928 9.653 18.897 9.931 ;
     RECT  16.704 9.923 16.794 10.021 ;
     RECT  19.62 9.925 29.106 10.049 ;
     RECT  2.268 9.823 10.782 10.157 ;
     RECT  19.62 10.049 20.574 10.157 ;
     RECT  19.728 10.157 20.574 10.163 ;
     RECT  16.704 10.021 16.902 10.193 ;
     RECT  2.268 10.157 10.746 10.355 ;
     RECT  17.676 9.931 18.897 10.355 ;
     RECT  20.016 10.163 20.574 10.355 ;
     RECT  16.776 10.193 16.902 10.597 ;
     RECT  21.672 10.049 29.106 10.603 ;
     RECT  16.776 10.597 17.19 10.697 ;
     RECT  16.776 10.697 17.118 10.769 ;
     RECT  21.672 10.603 29.682 10.795 ;
     RECT  14.868 10.831 14.886 10.867 ;
     RECT  20.052 10.355 20.574 10.867 ;
     RECT  21.672 10.795 29.754 10.867 ;
     RECT  20.052 10.867 29.754 11.021 ;
     RECT  2.304 10.355 10.746 11.101 ;
     RECT  20.088 11.021 29.754 11.129 ;
     RECT  17.928 10.355 18.897 11.137 ;
     RECT  14.868 10.867 14.958 11.173 ;
     RECT  0.396 11.083 0.414 11.179 ;
     RECT  14.832 11.173 14.958 11.201 ;
     RECT  0.288 11.179 0.414 11.213 ;
     RECT  20.088 11.129 20.574 11.261 ;
     RECT  17.928 11.137 19.134 11.273 ;
     RECT  2.304 11.101 11.43 11.281 ;
     RECT  0.288 11.213 0.306 11.309 ;
     RECT  17.928 11.273 19.062 11.399 ;
     RECT  16.776 10.769 16.794 11.407 ;
     RECT  20.196 11.261 20.574 11.453 ;
     RECT  2.304 11.281 11.466 11.515 ;
     RECT  17.928 11.399 19.026 11.551 ;
     RECT  16.524 11.407 16.794 11.641 ;
     RECT  17.784 11.551 19.026 11.641 ;
     RECT  13.215 2.413 13.497 11.713 ;
     RECT  16.524 11.641 19.026 11.789 ;
     RECT  2.304 11.515 11.538 11.821 ;
     RECT  14.832 11.201 14.922 11.849 ;
     RECT  2.304 11.821 11.754 11.947 ;
     RECT  12.6 11.713 13.497 11.947 ;
     RECT  17.532 11.789 19.026 11.984 ;
     RECT  20.556 11.453 20.574 12.055 ;
     RECT  20.556 12.055 20.754 12.091 ;
     RECT  21.528 11.129 29.754 12.091 ;
     RECT  14.832 11.849 14.886 12.209 ;
     RECT  20.556 12.091 29.754 12.427 ;
     RECT  16.524 11.789 16.794 12.451 ;
     RECT  20.556 12.427 29.826 12.479 ;
     RECT  20.556 12.479 21.366 12.523 ;
     RECT  1.26 12.427 1.278 12.619 ;
     RECT  2.304 11.947 13.497 12.721 ;
     RECT  20.304 12.523 21.366 12.721 ;
     RECT  17.532 11.984 18.99 12.793 ;
     RECT  1.152 12.619 1.278 12.797 ;
     RECT  16.308 12.451 16.794 12.829 ;
     RECT  17.532 12.793 19.278 12.829 ;
     RECT  16.308 12.829 19.278 12.857 ;
     RECT  16.38 12.857 19.278 12.859 ;
     RECT  20.232 12.721 21.366 12.859 ;
     RECT  16.38 12.859 21.366 12.893 ;
     RECT  14.868 12.209 14.886 12.901 ;
     RECT  14.868 12.901 14.922 12.991 ;
     RECT  16.38 12.893 21.114 13.019 ;
     RECT  14.832 12.991 14.922 13.091 ;
     RECT  16.38 13.019 18.918 13.091 ;
     RECT  2.304 12.721 13.554 13.099 ;
     RECT  19.944 13.019 21.114 13.199 ;
     RECT  19.944 13.199 20.25 13.325 ;
     RECT  16.38 13.091 16.578 13.469 ;
     RECT  0.252 12.907 0.27 13.483 ;
     RECT  14.832 13.091 14.85 13.559 ;
     RECT  1.692 13.099 13.554 13.567 ;
     RECT  0.252 13.483 0.414 13.579 ;
     RECT  22.104 12.479 29.826 13.595 ;
     RECT  0.216 13.579 0.414 13.613 ;
     RECT  0.216 13.613 0.342 13.631 ;
     RECT  0.252 13.631 0.342 13.661 ;
     RECT  20.988 13.199 21.114 13.711 ;
     RECT  22.104 13.595 23.274 13.711 ;
     RECT  17.388 13.091 18.918 13.801 ;
     RECT  1.692 13.567 13.626 13.819 ;
     RECT  1.692 13.819 14.13 13.865 ;
     RECT  20.988 13.711 23.274 13.865 ;
     RECT  17.388 13.801 18.954 13.945 ;
     RECT  17.1 13.945 18.954 13.981 ;
     RECT  19.944 13.325 20.034 13.981 ;
     RECT  14.868 13.909 14.886 14.099 ;
     RECT  17.1 13.981 20.034 14.251 ;
     RECT  17.1 14.251 20.286 14.285 ;
     RECT  24.015 13.595 29.826 14.347 ;
     RECT  0.252 13.661 0.27 14.539 ;
     RECT  1.692 13.865 13.95 14.611 ;
     RECT  19.656 14.285 20.286 14.611 ;
     RECT  24.015 14.347 29.97 14.635 ;
     RECT  21.276 13.865 22.338 14.675 ;
     RECT  22.176 14.675 22.338 14.683 ;
     RECT  23.184 13.865 23.274 14.683 ;
     RECT  17.1 14.285 18.897 14.711 ;
     RECT  21.276 14.675 21.438 14.881 ;
     RECT  22.176 14.683 23.274 14.909 ;
     RECT  16.308 14.827 16.326 14.989 ;
     RECT  22.32 14.909 23.274 15.025 ;
     RECT  24.015 14.635 30.042 15.025 ;
     RECT  1.692 14.611 14.85 15.061 ;
     RECT  17.424 14.711 18.897 15.061 ;
     RECT  19.656 14.611 20.358 15.061 ;
     RECT  16.308 14.989 16.578 15.179 ;
     RECT  22.32 15.025 30.042 15.179 ;
     RECT  16.524 15.179 16.578 15.188 ;
     RECT  0.252 14.539 0.414 15.211 ;
     RECT  1.692 15.061 14.922 15.215 ;
     RECT  17.424 15.061 20.358 15.223 ;
     RECT  21.096 14.881 21.438 15.223 ;
     RECT  0.216 15.211 0.414 15.245 ;
     RECT  0.216 15.245 0.234 15.341 ;
     RECT  16.524 15.188 16.542 15.359 ;
     RECT  22.32 15.179 22.842 15.359 ;
     RECT  17.424 15.223 21.438 15.529 ;
     RECT  1.692 15.215 14.85 15.593 ;
     RECT  17.424 15.529 21.582 15.719 ;
     RECT  17.928 15.719 21.582 15.791 ;
     RECT  22.5 15.359 22.806 15.791 ;
     RECT  17.928 15.791 20.502 16.097 ;
     RECT  1.728 15.593 14.85 16.141 ;
     RECT  1.728 16.141 15.282 16.231 ;
     RECT  21.564 15.791 21.582 16.259 ;
     RECT  22.5 15.791 22.518 16.295 ;
     RECT  19.908 16.097 20.502 16.331 ;
     RECT  17.928 16.097 19.098 16.403 ;
     RECT  1.728 16.231 15.39 16.835 ;
     RECT  23.724 15.179 30.042 16.979 ;
     RECT  19.908 16.331 20.394 17.177 ;
     RECT  22.824 17.149 22.842 17.339 ;
     RECT  20.16 17.177 20.394 17.411 ;
     RECT  29.376 16.979 30.042 17.609 ;
     RECT  20.16 17.411 20.178 18.059 ;
     RECT  17.928 16.403 18.897 18.149 ;
     RECT  2.376 16.835 15.39 18.571 ;
     RECT  23.724 16.979 28.53 18.689 ;
     RECT  23.724 18.689 27.99 18.761 ;
     RECT  23.724 18.761 27.81 18.959 ;
     RECT  23.724 18.959 27.774 19.031 ;
     RECT  23.724 19.031 26.046 19.139 ;
     RECT  23.724 19.139 25.686 19.229 ;
     RECT  26.856 19.031 27.774 19.229 ;
     RECT  29.376 17.609 29.394 19.229 ;
     RECT  24.015 19.229 25.686 19.499 ;
     RECT  27.36 19.229 27.774 19.499 ;
     RECT  2.376 18.571 15.75 19.651 ;
     RECT  25.668 19.499 25.686 19.679 ;
     RECT  2.376 19.651 15.858 21.973 ;
     RECT  2.304 21.973 15.858 23.189 ;
     RECT  2.415 23.189 15.858 23.701 ;
     RECT  2.415 23.701 16.038 23.971 ;
     RECT  2.415 23.971 16.146 24.475 ;
     RECT  2.415 24.475 16.29 25.321 ;
     RECT  2.304 25.321 16.29 25.555 ;
     RECT  2.304 25.555 16.434 26.519 ;
     RECT  2.304 26.519 16.218 27.245 ;
     RECT  2.304 27.245 16.074 27.635 ;
     RECT  18.615 18.149 18.897 27.827 ;
     RECT  24.015 19.499 24.297 27.827 ;
     RECT  2.415 27.635 16.074 27.905 ;
     RECT  2.415 27.905 15.39 27.965 ;
     RECT  2.415 27.965 15.354 28.061 ;
     RECT  2.415 28.061 15.066 28.097 ;
     RECT  18.615 27.827 18.705 28.097 ;
     RECT  24.015 27.827 24.105 28.097 ;
     RECT  2.88 28.097 15.066 28.541 ;
     RECT  13.356 28.541 15.066 28.925 ;
     RECT  2.88 28.541 12.582 29.069 ;
     RECT  7.776 29.069 9.018 29.117 ;
     RECT  9.972 29.069 12.582 29.117 ;
     RECT  2.88 29.069 6.894 29.165 ;
     RECT  2.88 29.165 6.03 29.693 ;
     RECT  6.876 29.165 6.894 29.693 ;
     RECT  8.244 29.117 9.018 29.693 ;
     RECT  10.08 29.117 12.51 29.693 ;
     RECT  13.356 28.925 14.706 29.693 ;
     RECT  3.6 29.693 3.618 29.741 ;
     RECT  5.616 29.693 5.634 29.741 ;
     RECT  8.46 29.693 8.91 29.741 ;
     RECT  10.08 29.693 10.098 29.741 ;
     RECT  11.7 29.693 12.51 29.741 ;
     RECT  13.608 29.693 13.626 29.741 ;
     RECT  11.7 29.741 11.718 29.789 ;
     RECT  12.456 29.741 12.51 29.789 ;
     RECT  8.46 29.741 8.478 30.125 ;
     RECT  12.564 29.995 12.582 30.125 ;
    LAYER M4 ;
     RECT  0.156 3.024 0.205 15.24 ;
     RECT  0.205 3.024 0.245 15.336 ;
     RECT  0.245 3.12 2.408 15.336 ;
     RECT  2.408 2.148 2.512 28.092 ;
     RECT  2.512 2.418 2.704 28.092 ;
     RECT  2.704 3.12 2.837 9 ;
     RECT  2.837 3.12 2.873 5.064 ;
     RECT  2.704 10.704 2.873 15.336 ;
     RECT  2.837 7.344 2.945 9 ;
     RECT  2.704 28.032 2.972 28.092 ;
     RECT  2.873 10.704 3.089 14.76 ;
     RECT  2.873 3.12 3.197 3.624 ;
     RECT  3.089 10.704 3.233 13.896 ;
     RECT  3.233 10.704 3.269 12.792 ;
     RECT  3.197 3.6 3.305 3.624 ;
     RECT  2.873 5.04 3.305 5.064 ;
     RECT  2.945 7.632 3.305 9 ;
     RECT  3.269 10.704 3.305 10.728 ;
     RECT  2.869 29.664 3.548 29.688 ;
     RECT  3.548 29.664 3.635 29.736 ;
     RECT  2.972 28.032 3.685 28.536 ;
     RECT  3.635 29.664 3.685 29.688 ;
     RECT  3.685 28.032 3.877 29.688 ;
     RECT  3.877 27.936 3.964 29.688 ;
     RECT  2.704 21.072 3.985 21.096 ;
     RECT  3.269 12.528 4.025 12.792 ;
     RECT  2.837 6.288 4.097 6.312 ;
     RECT  3.305 8.448 4.205 9 ;
     RECT  3.985 21.072 4.277 21.672 ;
     RECT  4.025 12.528 4.385 12.552 ;
     RECT  3.964 28.512 4.493 29.688 ;
     RECT  2.704 22.704 4.705 22.728 ;
     RECT  4.277 21.408 4.709 21.672 ;
     RECT  4.705 22.704 4.849 23.304 ;
     RECT  4.837 26.784 4.996 26.808 ;
     RECT  4.996 26.736 5.057 26.808 ;
     RECT  4.988 19.92 5.075 19.944 ;
     RECT  4.669 9.12 5.105 9.144 ;
     RECT  5.057 26.736 5.141 26.856 ;
     RECT  4.493 29.088 5.267 29.688 ;
     RECT  4.849 22.704 5.393 23.352 ;
     RECT  5.267 29.664 5.403 29.688 ;
     RECT  5.077 19.344 5.429 19.368 ;
     RECT  5.125 25.632 5.461 25.656 ;
     RECT  5.461 25.104 5.509 25.656 ;
     RECT  5.393 22.704 5.537 23.304 ;
     RECT  5.403 29.664 5.645 29.736 ;
     RECT  5.509 25.104 5.788 26.232 ;
     RECT  5.788 25.104 5.843 25.128 ;
     RECT  5.605 27.936 6.085 27.96 ;
     RECT  6.085 27.936 6.181 28.488 ;
     RECT  6.181 27.312 6.245 28.488 ;
     RECT  5.645 29.664 6.245 29.688 ;
     RECT  6.245 27.312 6.265 29.688 ;
     RECT  4.709 21.408 6.361 21.432 ;
     RECT  6.361 20.496 6.505 21.432 ;
     RECT  6.433 9.984 6.577 10.008 ;
     RECT  3.233 13.872 6.577 13.896 ;
     RECT  5.537 22.848 6.577 23.304 ;
     RECT  6.577 9.984 6.689 10.056 ;
     RECT  6.577 13.872 6.725 14.856 ;
     RECT  6.505 20.496 6.757 21.672 ;
     RECT  6.725 13.872 6.803 14.808 ;
     RECT  6.577 22.848 6.829 23.736 ;
     RECT  6.689 10.032 6.833 10.056 ;
     RECT  5.788 26.208 7.189 26.232 ;
     RECT  6.829 22.752 7.225 23.736 ;
     RECT  6.565 25.056 7.225 25.08 ;
     RECT  7.189 26.208 7.225 26.808 ;
     RECT  7.225 25.056 7.477 26.808 ;
     RECT  6.265 27.936 7.477 29.688 ;
     RECT  7.225 22.752 7.621 23.976 ;
     RECT  7.477 25.056 7.621 29.688 ;
     RECT  7.621 7.392 7.808 7.416 ;
     RECT  6.803 13.872 7.808 13.896 ;
     RECT  7.621 18.816 7.808 18.84 ;
     RECT  6.757 19.92 7.808 21.672 ;
     RECT  7.621 22.752 7.808 29.688 ;
     RECT  7.808 2.148 7.912 29.688 ;
     RECT  7.912 2.418 7.996 29.688 ;
     RECT  7.996 2.418 8.104 28.056 ;
     RECT  7.996 29.088 8.237 29.688 ;
     RECT  8.104 23.952 8.387 23.976 ;
     RECT  8.237 29.664 8.405 29.688 ;
     RECT  8.405 29.664 8.489 30.12 ;
     RECT  8.489 29.664 8.531 30.024 ;
     RECT  8.104 21.12 8.705 22.872 ;
     RECT  8.705 22.224 8.849 22.872 ;
     RECT  8.849 22.464 8.885 22.872 ;
     RECT  8.104 19.968 8.915 19.992 ;
     RECT  8.104 25.104 8.915 28.056 ;
     RECT  8.915 25.2 8.993 28.056 ;
     RECT  8.531 29.664 9.011 29.736 ;
     RECT  8.993 27.936 9.061 28.056 ;
     RECT  8.705 21.12 9.097 21.144 ;
     RECT  9.061 27.936 9.253 28.536 ;
     RECT  9.011 29.664 9.253 29.688 ;
     RECT  8.993 25.2 9.317 26.904 ;
     RECT  8.104 18.768 9.397 18.792 ;
     RECT  9.397 18.576 9.497 18.792 ;
     RECT  9.253 27.936 9.685 29.688 ;
     RECT  9.497 18.768 9.857 18.792 ;
     RECT  9.317 25.2 9.884 26.616 ;
     RECT  9.884 25.104 9.971 26.616 ;
     RECT  8.885 22.464 10.021 22.776 ;
     RECT  9.685 29.088 10.021 29.688 ;
     RECT  9.971 25.632 10.067 26.616 ;
     RECT  10.021 22.464 10.108 23.4 ;
     RECT  10.021 29.088 10.109 29.736 ;
     RECT  10.172 24.48 10.259 24.552 ;
     RECT  9.685 27.936 10.693 28.056 ;
     RECT  10.693 27.936 10.717 28.104 ;
     RECT  10.109 29.088 10.717 29.688 ;
     RECT  10.717 27.936 10.835 29.688 ;
     RECT  10.285 26.784 10.933 26.808 ;
     RECT  10.835 27.936 10.933 28.008 ;
     RECT  10.259 24.528 10.979 24.552 ;
     RECT  10.108 22.464 11.081 22.488 ;
     RECT  10.067 25.632 11.261 25.656 ;
     RECT  10.933 26.784 11.329 28.008 ;
     RECT  11.329 26.208 11.369 28.008 ;
     RECT  9.097 20.544 11.441 21.144 ;
     RECT  11.221 23.376 11.459 23.4 ;
     RECT  11.125 19.344 11.549 19.368 ;
     RECT  10.835 29.088 11.557 29.688 ;
     RECT  10.573 17.856 11.617 17.88 ;
     RECT  11.441 21.024 11.941 21.144 ;
     RECT  11.941 21.024 11.987 21.72 ;
     RECT  11.941 25.104 12.083 25.128 ;
     RECT  11.617 17.088 12.197 17.88 ;
     RECT  11.987 21.696 12.229 21.72 ;
     RECT  12.085 22.704 12.229 22.728 ;
     RECT  12.229 21.696 12.437 22.728 ;
     RECT  11.557 29.088 12.517 29.784 ;
     RECT  12.437 21.696 12.553 22.776 ;
     RECT  12.517 29.088 12.553 30.024 ;
     RECT  11.369 26.208 12.613 27.96 ;
     RECT  12.553 29.088 12.613 30.12 ;
     RECT  12.613 26.208 12.637 30.12 ;
     RECT  12.637 26.208 12.661 29.736 ;
     RECT  12.661 24.528 12.985 24.552 ;
     RECT  12.553 21.696 13.004 23.352 ;
     RECT  12.985 24.48 13.004 24.552 ;
     RECT  8.104 13.872 13.208 13.896 ;
     RECT  12.197 17.088 13.208 17.112 ;
     RECT  12.949 18.768 13.208 18.792 ;
     RECT  11.941 19.92 13.208 19.944 ;
     RECT  13.004 21.696 13.208 24.552 ;
     RECT  12.661 25.68 13.208 29.736 ;
     RECT  13.208 2.148 13.312 29.736 ;
     RECT  13.312 2.418 13.504 29.736 ;
     RECT  13.504 13.824 13.565 13.896 ;
     RECT  13.504 25.056 13.565 29.736 ;
     RECT  13.504 18.48 13.619 19.368 ;
     RECT  13.565 26.736 13.637 29.736 ;
     RECT  13.619 18.672 13.66 19.368 ;
     RECT  13.504 21.552 13.667 23.352 ;
     RECT  13.66 18.72 13.673 19.368 ;
     RECT  13.667 21.552 13.708 22.824 ;
     RECT  13.673 18.72 13.789 18.792 ;
     RECT  13.637 26.736 13.817 29.688 ;
     RECT  13.817 27.12 13.859 29.688 ;
     RECT  13.565 25.056 13.889 25.656 ;
     RECT  13.708 21.552 14.099 22.2 ;
     RECT  13.565 13.824 14.147 13.848 ;
     RECT  13.504 17.088 14.147 17.112 ;
     RECT  13.889 25.104 14.285 25.656 ;
     RECT  14.285 25.104 14.357 25.128 ;
     RECT  13.859 27.936 14.717 29.688 ;
     RECT  14.099 22.176 14.732 22.2 ;
     RECT  14.717 27.936 14.819 29.016 ;
     RECT  13.789 18.768 14.825 18.792 ;
     RECT  14.821 7.728 14.857 7.752 ;
     RECT  14.857 7.632 15.005 7.752 ;
     RECT  15.005 7.632 15.041 7.656 ;
     RECT  14.732 22.176 15.077 22.776 ;
     RECT  14.819 27.936 15.077 28.92 ;
     RECT  15.077 27.936 15.109 28.056 ;
     RECT  15.164 19.68 15.251 19.704 ;
     RECT  14.929 26.208 15.251 26.232 ;
     RECT  15.109 27.216 15.365 28.056 ;
     RECT  15.365 27.216 15.401 27.96 ;
     RECT  15.541 22.8 15.689 22.824 ;
     RECT  15.401 27.216 16.229 27.24 ;
     RECT  16.297 14.832 16.403 14.856 ;
     RECT  16.357 13.44 16.444 13.464 ;
     RECT  16.441 6.288 16.549 6.312 ;
     RECT  16.297 8.112 16.589 8.136 ;
     RECT  16.693 10.128 16.765 10.152 ;
     RECT  13.504 11.664 16.765 11.688 ;
     RECT  16.765 10.032 16.877 10.152 ;
     RECT  16.877 10.128 16.913 10.152 ;
     RECT  16.549 5.712 17.017 6.312 ;
     RECT  16.765 11.376 17.053 11.688 ;
     RECT  17.017 5.712 17.089 6.84 ;
     RECT  17.197 13.056 17.453 13.08 ;
     RECT  17.053 11.376 17.917 11.784 ;
     RECT  17.917 11.376 18.025 11.976 ;
     RECT  18.025 10.848 18.133 12.36 ;
     RECT  18.133 10.128 18.241 12.36 ;
     RECT  16.513 3.408 18.608 3.432 ;
     RECT  17.089 5.424 18.608 7.752 ;
     RECT  18.241 9.792 18.608 12.36 ;
     RECT  17.485 14.592 18.608 14.616 ;
     RECT  18.608 2.148 18.712 28.092 ;
     RECT  18.712 2.418 18.904 27.822 ;
     RECT  18.904 4.128 18.965 5.688 ;
     RECT  18.904 11.424 18.965 12.36 ;
     RECT  18.904 9.792 19.829 10.152 ;
     RECT  18.965 11.424 19.969 11.976 ;
     RECT  19.829 9.936 20.041 10.152 ;
     RECT  19.969 11.424 20.041 12.888 ;
     RECT  18.965 4.512 20.045 5.688 ;
     RECT  20.045 5.184 20.189 5.688 ;
     RECT  20.041 9.936 20.291 12.888 ;
     RECT  18.904 14.256 20.297 14.28 ;
     RECT  18.904 15.456 20.369 15.48 ;
     RECT  20.291 9.936 20.585 11.448 ;
     RECT  20.291 12.528 20.585 12.888 ;
     RECT  18.904 6.816 20.773 7.896 ;
     RECT  20.653 3.936 20.819 3.96 ;
     RECT  20.585 9.936 20.977 11.256 ;
     RECT  20.585 12.864 21.085 12.888 ;
     RECT  21.085 12.864 21.377 13.032 ;
     RECT  21.265 4.176 21.481 4.2 ;
     RECT  20.189 5.184 21.481 5.64 ;
     RECT  20.773 6.816 21.481 8.376 ;
     RECT  21.481 4.176 21.553 5.64 ;
     RECT  21.481 6.816 21.553 8.424 ;
     RECT  21.377 13.008 21.625 13.032 ;
     RECT  21.553 4.176 21.809 8.424 ;
     RECT  21.625 13.008 22.025 13.944 ;
     RECT  20.977 9.648 22.097 11.256 ;
     RECT  22.097 9.744 22.169 11.256 ;
     RECT  22.025 13.008 22.277 13.032 ;
     RECT  21.809 7.44 22.565 8.424 ;
     RECT  21.809 4.176 22.601 6.024 ;
     RECT  21.949 2.832 22.637 2.856 ;
     RECT  22.601 5.184 22.673 6.024 ;
     RECT  22.673 5.616 22.777 6.024 ;
     RECT  22.169 10.032 22.813 11.256 ;
     RECT  22.601 4.176 22.853 4.2 ;
     RECT  22.813 10.032 22.889 11.4 ;
     RECT  22.565 7.44 22.961 7.656 ;
     RECT  22.777 5.616 23.929 6.264 ;
     RECT  23.281 3.312 24.008 3.336 ;
     RECT  23.929 5.616 24.008 6.312 ;
     RECT  22.961 7.44 24.008 7.512 ;
     RECT  22.889 10.128 24.008 11.4 ;
     RECT  22.165 14.352 24.008 14.376 ;
     RECT  24.008 2.148 24.112 28.092 ;
     RECT  24.112 2.418 24.304 27.822 ;
     RECT  24.304 12.432 25.445 14.952 ;
     RECT  24.304 4.752 25.477 7.704 ;
     RECT  24.304 8.736 25.477 11.16 ;
     RECT  25.445 12.432 25.477 14.232 ;
     RECT  24.304 2.592 25.657 3.768 ;
     RECT  25.477 4.752 25.657 14.232 ;
     RECT  25.657 2.592 25.697 14.232 ;
     RECT  25.513 16.032 26.269 16.056 ;
     RECT  25.697 3.072 26.773 14.232 ;
     RECT  26.269 15.408 26.773 16.056 ;
     RECT  26.773 3.072 26.813 16.056 ;
     RECT  26.813 3.072 26.957 15.576 ;
     RECT  26.957 3.072 27.389 12.264 ;
     RECT  26.957 13.392 27.389 15.576 ;
     RECT  27.389 8.304 27.925 12.264 ;
     RECT  27.389 13.392 27.925 14.904 ;
     RECT  27.925 8.304 28.429 14.904 ;
     RECT  28.429 8.304 28.501 15.048 ;
     RECT  27.389 3.072 29.041 7.272 ;
     RECT  28.501 8.304 29.041 15.144 ;
     RECT  29.041 3.072 29.365 15.144 ;
     RECT  29.365 3.072 29.653 15.24 ;
     RECT  29.653 3.024 29.725 15.24 ;
     RECT  29.725 2.88 29.837 15.24 ;
     RECT  29.837 3.024 30.06 15.24 ;
     RECT  30.06 6.24 30.125 6.264 ;
    LAYER M5 ;
     RECT  2.4 2.137 2.52 2.151 ;
     RECT  7.8 2.137 7.92 2.151 ;
     RECT  13.2 2.137 13.32 2.151 ;
     RECT  18.6 2.137 18.72 2.151 ;
     RECT  24 2.137 24.12 2.151 ;
     RECT  2.4 2.151 2.712 3.733 ;
     RECT  7.8 2.151 8.112 7.381 ;
     RECT  20.784 3.925 20.808 8.341 ;
     RECT  20.784 8.341 21.144 8.387 ;
     RECT  18.6 2.151 18.912 9.781 ;
     RECT  2.4 3.733 2.856 10.835 ;
     RECT  21.12 8.387 21.144 10.837 ;
     RECT  18.288 9.781 18.912 10.883 ;
     RECT  20.256 10.837 21.144 10.883 ;
     RECT  0.192 11.125 0.216 11.315 ;
     RECT  13.2 2.151 13.512 11.653 ;
     RECT  26.448 11.125 26.472 11.749 ;
     RECT  26.352 11.749 26.472 12.517 ;
     RECT  2.4 10.835 2.712 12.565 ;
     RECT  1.152 12.517 1.176 12.707 ;
     RECT  2.4 12.565 2.808 13.187 ;
     RECT  0.912 13.717 0.936 13.861 ;
     RECT  7.632 7.381 8.112 14.245 ;
     RECT  20.256 10.883 20.28 14.291 ;
     RECT  2.4 13.187 2.712 14.485 ;
     RECT  0.912 13.861 1.032 14.629 ;
     RECT  2.4 14.485 2.808 14.771 ;
     RECT  0.288 14.629 1.032 14.819 ;
     RECT  6.768 14.245 8.112 14.819 ;
     RECT  16.368 13.429 16.392 14.867 ;
     RECT  26.352 12.517 26.808 15.443 ;
     RECT  26.448 15.443 26.472 16.019 ;
     RECT  13.2 11.653 14.136 17.123 ;
     RECT  13.2 17.123 13.512 18.469 ;
     RECT  13.2 18.469 13.608 18.709 ;
     RECT  7.632 14.819 8.112 18.757 ;
     RECT  9.408 18.565 9.432 18.757 ;
     RECT  11.952 17.605 11.976 19.333 ;
     RECT  5.088 19.333 5.112 19.909 ;
     RECT  7.632 18.757 9.432 19.909 ;
     RECT  6.768 19.909 9.432 20.003 ;
     RECT  5.04 19.909 5.112 21.443 ;
     RECT  13.2 18.709 13.752 21.541 ;
     RECT  11.136 19.333 11.976 21.731 ;
     RECT  13.2 21.541 14.088 22.117 ;
     RECT  12.24 22.117 14.088 22.211 ;
     RECT  6.768 20.003 8.112 22.213 ;
     RECT  9.408 20.003 9.432 22.213 ;
     RECT  11.136 21.731 11.16 22.693 ;
     RECT  12.24 22.211 13.752 22.693 ;
     RECT  15.216 19.669 15.24 22.741 ;
     RECT  6.768 22.213 9.432 23.365 ;
     RECT  6.768 23.365 10.056 24.469 ;
     RECT  11.136 22.693 13.752 24.469 ;
     RECT  6.768 24.469 13.752 25.045 ;
     RECT  5.088 21.443 5.112 25.093 ;
     RECT  6.576 25.045 13.752 25.093 ;
     RECT  5.088 25.093 13.752 25.141 ;
     RECT  14.784 22.741 15.24 25.141 ;
     RECT  5.088 25.141 15.24 26.243 ;
     RECT  5.088 26.243 14.808 26.725 ;
     RECT  5.04 26.725 14.808 26.773 ;
     RECT  4.848 26.773 14.808 27.205 ;
     RECT  4.848 27.205 15.144 27.925 ;
     RECT  2.4 14.771 2.712 28.021 ;
     RECT  3.888 27.925 15.144 28.021 ;
     RECT  18.6 10.883 18.912 28.089 ;
     RECT  24 2.151 24.312 28.089 ;
     RECT  2.4 28.021 15.24 28.103 ;
     RECT  18.6 28.089 18.72 28.103 ;
     RECT  24 28.089 24.12 28.103 ;
     RECT  3.024 28.103 15.24 30.096 ;
     RECT  8.448 30.096 8.472 30.131 ;
     RECT  12.576 30.096 12.6 30.131 ;
     RECT  18.912 10.837 20.256 14.291 ;
     RECT  1.176 12.517 2.4 12.707 ;
     RECT  1.152 12.707 2.4 13.717 ;
     RECT  2.712 13.187 2.808 14.485 ;
     RECT  0.936 13.717 2.4 13.861 ;
     RECT  1.032 13.861 2.4 14.771 ;
     RECT  1.08 14.771 2.4 14.819 ;
     RECT  13.512 17.123 13.608 18.469 ;
     RECT  11.976 17.605 13.2 21.731 ;
     RECT  8.112 18.565 9.408 18.757 ;
     RECT  13.752 19.669 15.216 21.541 ;
     RECT  8.112 20.003 9.408 22.213 ;
     RECT  14.088 21.541 15.216 22.211 ;
     RECT  11.16 21.731 13.2 22.117 ;
     RECT  11.16 22.117 12.24 22.693 ;
     RECT  13.752 22.211 15.216 22.741 ;
     RECT  13.752 22.741 14.784 25.141 ;
     RECT  10.056 23.365 11.136 24.469 ;
     RECT  5.112 25.045 6.576 25.093 ;
     RECT  14.808 26.243 15.144 27.205 ;
     RECT  2.712 27.925 3.888 28.021 ;
  END
END ot_smh_tr_w128_s1_m0
END LIBRARY
